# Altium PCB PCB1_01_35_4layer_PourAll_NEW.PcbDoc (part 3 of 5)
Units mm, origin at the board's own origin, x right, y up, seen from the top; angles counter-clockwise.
Board outline 26.5 x 17 mm, 4 copper layers (Top Layer, Layer 1, Layer 2, Bottom Layer), stack 0.603 mm thick; 0 components, 1 nets, 8 pads, 81 vias.

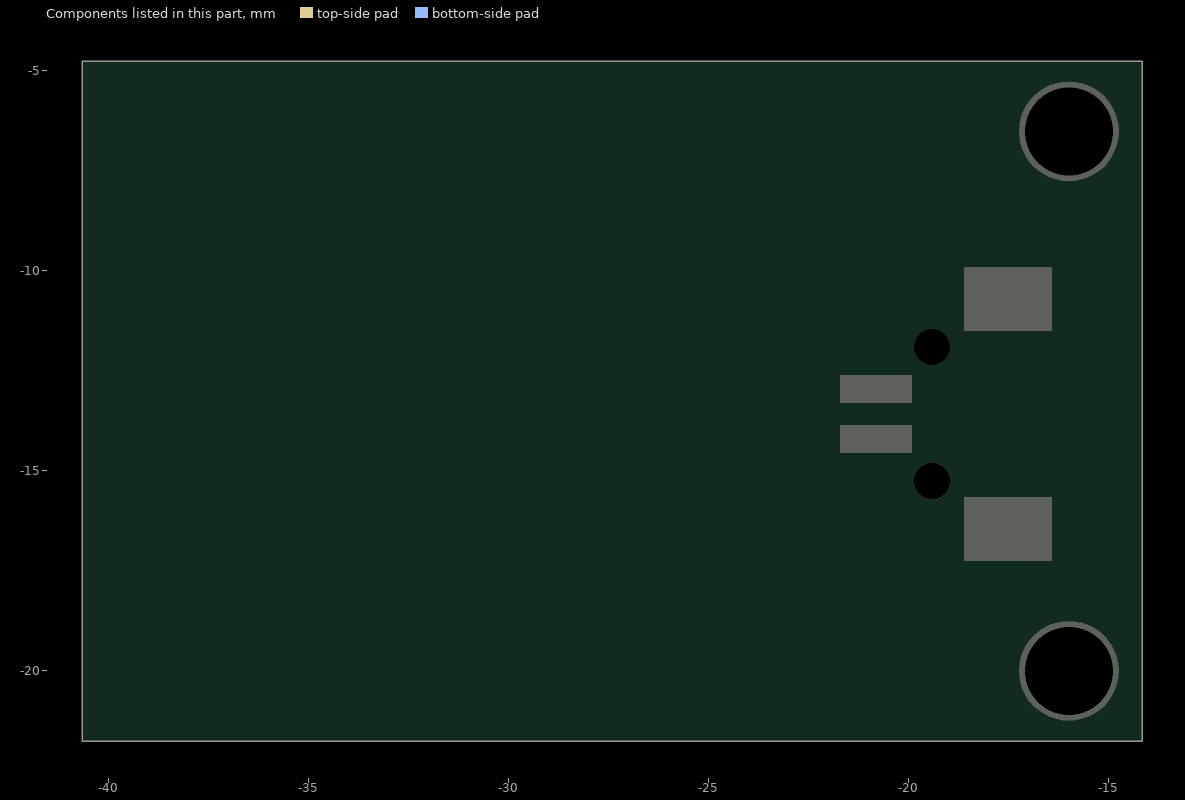
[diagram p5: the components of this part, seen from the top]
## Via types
v1: diameter 0.5, hole 0.3, Top Layer to Bottom Layer, tented both sides, 68 vias
v2: diameter 1, hole 0.5, Top Layer to Bottom Layer, 9 vias
v3: diameter 0.65, hole 0.3, Top Layer to Bottom Layer, 4 vias

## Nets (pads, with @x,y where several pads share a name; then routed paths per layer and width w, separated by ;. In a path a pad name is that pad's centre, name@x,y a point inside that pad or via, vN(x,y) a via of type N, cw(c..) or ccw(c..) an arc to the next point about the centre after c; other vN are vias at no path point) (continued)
copper on no net: (continued)
  Layer 2 w0.1: -34.932,-14.453 ccw(c-31.735,-13.27) -34.612,-15.099 ccw(c-31.883,-13.367) -34.162,-15.658 ccw(c-32.001,-13.479) -33.598,-16.1 ccw(c-31.896,-13.305) -32.95,-16.403 ccw(c-31.853,-13.187) -32.254,-16.561 ccw(c-31.856,-13.236) -31.541,-16.57 ccw(c-31.836,-13.435) -30.846,-16.424 ccw(c-31.819,-13.511) -30.204,-16.123 ccw(c-31.96,-13.292) -29.192,-15.147 ccw(c-31.916,-13.315) -28.864,-14.523 ccw(c-31.713,-13.393) -28.681,-13.844 ccw(c-31.734,-13.399) -28.66,-13.144 ccw(c-31.923,-13.413) -28.792,-12.456 ccw(c-31.977,-13.427) -29.065,-11.813 ccw(c-31.874,-13.368) -29.466,-11.243 ccw(c-31.708,-13.22) -29.984,-10.779 ccw(c-31.766,-13.312) -30.592,-10.446 ccw(c-31.831,-13.467) -31.257,-10.253 ccw(c-31.836,-13.485) -31.947,-10.203 ccw(c-31.859,-13.228) -33.269,-10.55 ccw(c-31.81,-13.294) -33.835,-10.937 ccw(c-31.719,-13.402) -34.305,-11.436 ccw(c-31.735,-13.393) -34.659,-12.021 ccw(c-31.894,-13.32) -34.879,-12.665 ccw(c-32.028,-13.286) -34.945,-13.342 ccw(c-31.832,-13.282) -34.858,-14.015 ccw(c-31.723,-13.258) -34.631,-14.653 ccw(c-31.772,-13.284) -34.276,-15.228 ccw(c-31.925,-13.405) -33.805,-15.71 ccw(c-31.965,-13.44) -33.238,-16.07 ccw(c-31.863,-13.222) -31.942,-16.384 ccw(c-31.86,-13.281) -31.276,-16.329 ccw(c-31.819,-13.487) -30.641,-16.13 ccw(c-31.843,-13.454) -30.07,-15.791 ccw(c-31.947,-13.314) -29.587,-15.337 ccw(c-31.979,-13.283) -29.211,-14.792 ccw(c-31.872,-13.339) -28.959,-14.181 ccw(c-31.672,-13.397) -28.851,-13.532 ccw(c-31.792,-13.396) -28.894,-12.877 ccw(c-31.943,-13.421) -29.077,-12.247 ccw(c-31.952,-13.422) -29.388,-11.671 ccw(c-31.754,-13.271) -30.337,-10.791 ccw(c-31.791,-13.358) -30.933,-10.535 ccw(c-31.83,-13.479) -31.57,-10.412 ccw(c-31.83,-13.452) -32.216,-10.426 ccw(c-31.853,-13.283) -32.843,-10.578 ccw(c-31.887,-13.174) -33.416,-10.869 ccw(c-31.747,-13.374) -34.303,-11.784 ccw(c-31.767,-13.369) -34.582,-12.359 ccw(c-31.946,-13.307) -34.728,-12.979 ccw(c-31.974,-13.295) -34.728,-13.614 ccw(c-31.755,-13.267) -34.321,-14.807 ccw(c-31.811,-13.306) -33.941,-15.31 ccw(c-31.957,-13.444) -33.46,-15.716 ccw(c-31.931,-13.392) -32.9,-15.999 ccw(c-31.874,-13.242) -32.293,-16.154 ccw(c-31.867,-13.209) -31.668,-16.178 ccw(c-31.857,-13.33) -31.054,-16.069 ccw(c-31.802,-13.516) -30.482,-15.826 ccw(c-31.869,-13.407) -29.982,-15.46 ccw(c-31.961,-13.303) -29.573,-14.996 ccw(c-31.96,-13.302) -29.271,-14.457 ccw(c-31.736,-13.385) -29.051,-13.256 ccw(c-31.839,-13.398) -29.149,-12.652 ccw(c-31.949,-13.427) -29.373,-12.083 ccw(c-31.92,-13.41) -29.711,-11.575 ccw(c-31.793,-13.302) -30.149,-11.154 ccw(c-31.734,-13.235) -30.67,-10.845 ccw(c-31.822,-13.443) -31.847,-10.601 ccw(c-31.827,-13.413) -32.445,-10.67 ccw(c-31.869,-13.235) -33.012,-10.867 ccw(c-31.865,-13.225) -33.517,-11.189 ccw(c-31.737,-13.379) -34.26,-12.114 ccw(c-31.806,-13.348) -34.468,-12.671 ccw(c-31.991,-13.302) -34.546,-13.258 ccw(c-31.919,-13.298) -34.489,-13.846 ccw(c-31.775,-13.268) -34.306,-14.406 ccw(c-31.753,-13.26) -34.009,-14.915 ccw(c-31.849,-13.333) -33.613,-15.347 ccw(c-31.967,-13.467) -33.131,-15.678 ccw(c-31.907,-13.349) -32.588,-15.891 ccw(c-31.873,-13.228) -32.013,-15.981 ccw(c-31.872,-13.236) -31.433,-15.95 ccw(c-31.847,-13.377) -30.876,-15.795 ccw(c-31.8,-13.504) -30.37,-15.518 ccw(c-31.894,-13.372) -29.94,-15.136 ccw(c-31.967,-13.304) -29.601,-14.671 ccw(c-31.933,-13.321) -29.369,-14.147 ccw(c-31.778,-13.37) -29.256,-13.588 ccw(c-31.713,-13.382) -29.274,-13.019 ccw(c-31.917,-13.416) -29.673,-11.963 ccw(c-31.887,-13.391) -30.029,-11.524 ccw(c-31.764,-13.265) -30.471,-11.175 ccw(c-31.764,-13.279) -30.98,-10.937 ccw(c-31.813,-13.421) -31.527,-10.817 ccw(c-31.819,-13.465) -32.086,-10.814 ccw(c-31.831,-13.37) -32.632,-10.929 ccw(c-31.887,-13.2) -33.136,-11.163 ccw(c-31.84,-13.269) -33.572,-11.504 ccw(c-31.747,-13.364) -33.924,-11.931 ccw(c-31.736,-13.374) -34.177,-12.421 ccw(c-31.933,-13.309) -34.339,-13.499 ccw(c-31.874,-13.294) -34.234,-14.035 ccw(c-31.767,-13.262) -34.017,-14.536 ccw(c-31.779,-13.271) -33.701,-14.978 ccw(c-31.882,-13.365) -33.298,-15.341 ccw(c-31.951,-13.455) -32.825,-15.602 ccw(c-31.893,-13.313) -32.307,-15.749 ccw(c-31.877,-13.226) -31.77,-15.783 ccw(c-31.873,-13.27) -31.24,-15.704 ccw(c-31.833,-13.42) -30.742,-15.512 ccw(c-31.818,-13.464) -30.302,-15.212 ccw(c-31.944,-13.323) -29.669,-14.368 ccw(c-31.899,-13.339) -29.501,-13.867 ccw(c-31.735,-13.374) -29.447,-13.343 ccw(c-31.763,-13.381) -29.515,-12.823 ccw(c-31.896,-13.412) -29.694,-12.331 ccw(c-31.928,-13.426) -29.972,-11.888 ccw(c-31.854,-13.366) -30.336,-11.516 ccw(c-31.748,-13.237) -30.773,-11.236 ccw(c-31.785,-13.32) -31.261,-11.064 ccw(c-31.813,-13.436) -31.773,-11.001 ccw(c-31.815,-13.443) -32.286,-11.046 ccw(c-31.863,-13.251) -33.216,-11.459 ccw(c-31.815,-13.301) -33.585,-11.809 ccw(c-31.74,-13.366) -33.87,-12.231 ccw(c-31.759,-13.358) -34.06,-12.701 ccw(c-31.89,-13.322) -34.144,-13.199 ccw(c-31.982,-13.313) -34.112,-13.701 ccw(c-31.797,-13.275) -33.728,-14.621 ccw(c-31.807,-13.288) -33.401,-14.999 ccw(c-31.908,-13.398) -33.001,-15.294 ccw(c-31.927,-13.418) -32.545,-15.49 ccw(c-31.881,-13.254) -31.566,-15.565 ccw(c-31.87,-13.306) -31.089,-15.447 ccw(c-31.815,-13.455) -30.651,-15.227 ccw(c-31.842,-13.423) -30.277,-14.914 ccw(c-31.931,-13.337) -29.98,-14.528 ccw(c-31.952,-13.323) -29.772,-14.09 ccw(c-31.862,-13.353) -29.662,-13.619 ccw(c-31.71,-13.371) -29.66,-13.136 ccw(c-31.805,-13.384) -29.768,-12.669 ccw(c-31.906,-13.419) -29.974,-12.236 ccw(c-31.907,-13.417) -30.265,-11.856 ccw(c-31.778,-13.282) -31.051,-11.334 ccw(c-31.798,-13.354) -31.51,-11.22 ccw(c-31.811,-13.44) -31.981,-11.206 ccw(c-31.814,-13.415) -32.444,-11.291 ccw(c-31.853,-13.291) -32.875,-11.473 ccw(c-31.884,-13.225) -33.252,-11.748 ccw(c-31.765,-13.349) -33.78,-12.506 ccw(c-31.788,-13.343) -33.913,-12.949 ccw(c-31.928,-13.319) -33.945,-13.409 ccw(c-31.938,-13.313) -33.871,-13.862 ccw(c-31.793,-13.27) -33.443,-14.664 ccw(c-31.835,-13.31) -33.115,-14.978 ccw(c-31.927,-13.431) -32.726,-15.21 ccw(c-31.929,-13.42) -32.296,-15.345 ccw(c-31.898,-13.236) -31.404,-15.325 ccw(c-31.89,-13.25) -30.982,-15.178 ccw(c-31.785,-13.449) -30.29,-14.632 ccw(c-31.837,-13.42) -30.059,-14.256 ccw(c-31.979,-13.355) -29.858,-13.405 ccw(c-31.913,-13.354) -29.894,-12.969 ccw(c-31.758,-13.323) -30.024,-12.554 ccw(c-31.691,-13.299) -30.246,-12.182 ccw(c-31.803,-13.385) -30.546,-11.871 ccw(c-31.872,-13.467) -30.905,-11.631 ccw(c-31.876,-13.471) -31.304,-11.471 ccw(c-31.848,-13.369) -31.726,-11.398 ccw(c-31.839,-13.206) -32.151,-11.422 ccw(c-31.831,-13.221) -32.557,-11.544 ccw(c-31.776,-13.347) -32.925,-11.753 ccw(c-31.73,-13.414) -33.241,-12.034 ccw(c-31.752,-13.396) -33.491,-12.372 ccw(c-31.863,-13.332) -33.662,-12.754 ccw(c-32.005,-13.286) -33.741,-13.164 ccw(c-31.916,-13.29) -33.722,-13.578 ccw(c-31.76,-13.262) -33.426,-14.346 ccw(c-31.792,-13.287) -33.168,-14.665 ccw(c-31.892,-13.389) -32.847,-14.92 ccw(c-31.948,-13.472) -32.478,-15.092 ccw(c-31.909,-13.353) -32.081,-15.175 ccw(c-31.898,-13.244) -31.675,-15.17 ccw(c-31.899,-13.224) -31.281,-15.083 ccw(c-31.87,-13.307) -30.915,-14.917 ccw(c-31.792,-13.437) -30.597,-14.674 ccw(c-31.78,-13.457) -30.346,-14.365 ccw(c-31.889,-13.387) -30.171,-14.009 ccw(c-31.971,-13.356) -30.076,-13.624 ccw(c-31.958,-13.357) -30.061,-13.23 ccw(c-31.848,-13.348) -30.13,-12.843 ccw(c-31.705,-13.306) -30.284,-12.484 ccw(c-31.75,-13.337) -30.516,-12.172 ccw(c-31.863,-13.447) -31.151,-11.735 ccw(c-31.86,-13.429) -31.52,-11.624 ccw(c-31.832,-13.235) -32.279,-11.657 ccw(c-31.81,-13.285) -32.63,-11.802 ccw(c-31.758,-13.381) -32.941,-12.019 ccw(c-31.739,-13.406) -33.199,-12.294 ccw(c-31.795,-13.364) -33.394,-12.616 ccw(c-31.921,-13.306) -33.513,-12.971 ccw(c-31.974,-13.29) -33.545,-13.342 ccw(c-31.855,-13.287) -33.492,-13.709 ccw(c-31.767,-13.265) -33.363,-14.055 ccw(c-31.765,-13.266) -33.167,-14.367 ccw(c-31.838,-13.324) -32.91,-14.629 ccw(c-31.927,-13.434) -32.603,-14.826 ccw(c-31.923,-13.415) -32.26,-14.945 ccw(c-31.898,-13.302) -31.9,-14.984 ccw(c-31.897,-13.235) -31.541,-14.948 ccw(c-31.89,-13.261) -31.199,-14.839 ccw(c-31.844,-13.363) -30.889,-14.66 ccw(c-31.769,-13.466) -30.63,-14.416 ccw(c-31.831,-13.417) -30.436,-14.121 ccw(c-31.95,-13.359) -30.258,-13.443 ccw(c-31.911,-13.358) -30.277,-13.093 ccw(c-31.788,-13.338) -30.371,-12.758 ccw(c-31.712,-13.31) -30.54,-12.456 ccw(c-31.798,-13.373) -30.773,-12.202 ccw(c-31.858,-13.44) -31.053,-12.003 ccw(c-31.866,-13.452) -31.368,-11.867 ccw(c-31.844,-13.378) -31.702,-11.8 ccw(c-31.833,-13.248) -32.041,-11.809 ccw(c-31.831,-13.233) -32.366,-11.897 ccw(c-31.791,-13.333) -32.662,-12.055 ccw(c-31.752,-13.393) -32.918,-12.271 ccw(c-31.762,-13.384) -33.123,-12.534 ccw(c-31.844,-13.334) -33.267,-12.832 ccw(c-31.963,-13.292) -33.339,-13.154 ccw(c-31.913,-13.294) -33.333,-13.482 ccw(c-31.785,-13.275) -33.116,-14.093 ccw(c-31.8,-13.288) -32.918,-14.35 ccw(c-31.916,-13.408) -32.385,-14.701 ccw(c-31.905,-13.36) -32.076,-14.774 ccw(c-31.893,-13.272) -31.758,-14.779 ccw(c-31.895,-13.248) -31.447,-14.719 ccw(c-31.876,-13.307) -31.157,-14.596 ccw(c-31.818,-13.41) -30.903,-14.413 ccw(c-31.792,-13.443) -30.7,-14.177 ccw(c-31.874,-13.388) -30.557,-13.903 ccw(c-31.941,-13.361) -30.475,-13.606 ccw(c-31.94,-13.36) -30.456,-13.299 ccw(c-31.859,-13.356) -30.501,-12.997 ccw(c-31.743,-13.325) -30.613,-12.714 ccw(c-31.759,-13.338) -30.787,-12.468 ccw(c-31.83,-13.4) -31.01,-12.266 ccw(c-31.862,-13.443) -31.269,-12.117 ccw(c-31.853,-13.419) -31.553,-12.024 ccw(c-31.833,-13.326) -31.847,-11.994 ccw(c-31.834,-13.221) -32.14,-12.033 ccw(c-31.816,-13.286) -32.413,-12.137 ccw(c-31.766,-13.379) -32.86,-12.505 ccw(c-31.795,-13.358) -33.015,-12.748 ccw(c-31.889,-13.312) -33.114,-13.018 ccw(c-31.95,-13.294) -33.146,-13.301 ccw(c-31.864,-13.294) -33.113,-13.583 ccw(c-31.794,-13.278) -33.021,-13.85 ccw(c-31.785,-13.275) -32.877,-14.092 ccw(c-31.837,-13.316) -32.687,-14.296 ccw(c-31.908,-13.399) -32.457,-14.452 ccw(c-31.915,-13.403) -32.199,-14.549 ccw(c-31.894,-13.32) -31.927,-14.586 ccw(c-31.892,-13.264) -31.654,-14.565 ccw(c-31.889,-13.277) -31.393,-14.489 ccw(c-31.857,-13.352) -31.156,-14.36 ccw(c-31.798,-13.437) -30.955,-14.181 ccw(c-31.832,-13.41) -30.803,-13.962 ccw(c-31.922,-13.364) -30.657,-13.456 ccw(c-31.903,-13.363) -30.665,-13.193 ccw(c-31.767,-13.338) -30.849,-12.71 ccw(c-31.798,-13.365) -31.018,-12.516 ccw(c-31.846,-13.416) -31.224,-12.363 ccw(c-31.855,-13.43) -31.456,-12.257 ccw(c-31.839,-13.38) -31.703,-12.201 ccw(c-31.828,-13.283) -31.955,-12.201 ccw(c-31.829,-13.252) -32.198,-12.26 ccw(c-31.802,-13.324) -32.42,-12.371 ccw(c-31.772,-13.372) -32.612,-12.527 ccw(c-31.775,-13.37) -32.768,-12.717 ccw(c-31.832,-13.334) -32.879,-12.935 ccw(c-31.923,-13.299) -32.938,-13.17 ccw(c-31.904,-13.299) -32.94,-13.411 ccw(c-31.809,-13.287) -32.791,-13.862 ccw(c-31.812,-13.291) -32.651,-14.053 ccw(c-31.87,-13.345) -32.475,-14.208 ccw(c-31.918,-13.413) -32.269,-14.318 ccw(c-31.899,-13.362) -32.046,-14.377 ccw(c-31.889,-13.282) -31.589,-14.346 ccw(c-31.879,-13.313) -31.378,-14.262 ccw(c-31.839,-13.388) -31.192,-14.135 ccw(c-31.837,-13.397) -31.041,-13.969 ccw(c-31.879,-13.365) -30.931,-13.774 ccw(c-31.859,-13.371) -30.847,-13.343 ; -34.932,-14.453 cw(c-31.726,-13.264) -35.11,-13.754 cw(c-31.881,-13.284) -35.134,-13.032 cw(c-32.049,-13.274) -34.993,-12.321 cw(c-31.842,-13.342) -34.696,-11.659 cw(c-31.712,-13.416) -34.262,-11.074 cw(c-31.732,-13.394) -33.715,-10.592 cw(c-31.836,-13.244) -33.076,-10.24 cw(c-31.878,-13.16) -32.371,-10.042 cw(c-31.841,-13.391) -31.638,-10.007 cw(c-31.842,-13.484) -30.226,-10.398 cw(c-31.729,-13.262) -29.616,-10.813 cw(c-31.739,-13.259) -29.117,-11.358 cw(c-31.919,-13.392) -28.748,-12.002 cw(c-31.951,-13.413) -28.451,-13.451 cw(c-31.67,-13.411) -28.546,-14.19 cw(c-31.77,-13.378) -28.809,-14.89 cw(c-31.953,-13.287) -29.219,-15.517 cw(c-31.986,-13.263) -29.752,-16.047 cw(c-31.9,-13.373) -30.385,-16.451 cw(c-31.808,-13.56) -31.096,-16.702 cw(c-31.846,-13.376) -31.846,-16.785 cw(c-31.848,-13.197) -32.599,-16.706 cw(c-31.851,-13.196) -33.32,-16.47 cw(c-31.922,-13.351) -33.974,-16.085 cw(c-32.016,-13.482) -34.525,-15.559 cw(c-31.835,-13.333) -34.944,-14.922 cw(c-31.704,-13.263) -35.219,-14.208 cw(c-31.744,-13.271) -35.339,-13.451 cw(c-31.941,-13.28) -35.291,-12.686 cw(c-32.017,-13.274) -35.068,-11.95 cw(c-31.793,-13.37) -34.687,-11.28 cw(c-31.722,-13.415) -33.546,-10.249 cw(c-31.86,-13.182) -32.835,-9.943 cw(c-31.861,-13.214) -32.07,-9.807 cw(c-31.845,-13.443) -31.293,-9.842 cw(c-31.841,-13.468) -29.842,-10.394 cw(c-31.684,-13.214) -29.241,-10.895 cw(c-31.785,-13.3) -28.769,-11.522 cw(c-31.962,-13.408) -28.443,-12.237 cw(c-31.993,-13.421) -28.274,-13.007 cw(c-31.838,-13.406) -28.273,-13.795 cw(c-31.718,-13.407) -28.799,-15.276 cw(c-31.98,-13.259) -29.292,-15.899 cw(c-31.975,-13.268) -29.906,-16.404 cw(c-31.874,-13.425) -30.615,-16.766 cw(c-31.816,-13.563) -31.39,-16.958 cw(c-31.848,-13.315) -32.189,-16.97 cw(c-31.837,-13.169) -32.975,-16.813 cw(c-31.855,-13.219) -33.712,-16.494 cw(c-31.962,-13.403) -34.362,-16.021 cw(c-31.991,-13.449) -34.888,-15.41 cw(c-31.783,-13.306) -35.266,-14.697 cw(c-31.718,-13.273) -35.537,-13.11 cw(c-32.01,-13.265) -35.409,-12.308 cw(c-31.957,-13.291) -35.099,-11.557 cw(c-31.751,-13.403) -34.631,-10.889 cw(c-31.738,-13.403) -33.329,-9.915 cw(c-31.875,-13.118) -32.549,-9.666 cw(c-31.851,-13.278) -31.731,-9.601 cw(c-31.855,-13.488) -30.915,-9.715 cw(c-31.858,-13.511) -30.14,-9.997 cw(c-31.781,-13.359) -29.443,-10.438 cw(c-31.728,-13.269) -28.43,-11.734 cw(c-32,-13.415) -28.157,-12.519 cw(c-31.978,-13.413) -28.054,-13.345 cw(c-31.776,-13.412) -28.132,-14.174 cw(c-31.643,-13.433) -28.398,-14.965 cw(c-31.882,-13.321) -28.835,-15.678 cw(c-31.997,-13.236) -29.415,-16.284 cw(c-31.956,-13.288) -30.11,-16.756 cw(c-31.85,-13.49) -30.892,-17.064 cw(c-31.833,-13.515) -31.725,-17.185 cw(c-31.842,-13.256) -32.567,-17.12 cw(c-31.838,-13.196) -34.12,-16.47 cw(c-32.013,-13.456) -34.755,-15.907 cw(c-31.941,-13.405) -35.244,-15.212 cw(c-31.733,-13.289) -35.572,-14.425 cw(c-31.677,-13.269) -35.728,-13.585 cw(c-31.827,-13.278) -35.701,-12.732 cw(c-32.07,-13.244) -35.484,-11.903 cw(c-31.895,-13.318) -35.082,-11.146 cw(c-31.719,-13.435) -34.526,-10.49 cw(c-31.708,-13.443) -33.843,-9.964 cw(c-31.803,-13.283) -33.064,-9.597 cw(c-31.872,-13.09) -32.219,-9.416 cw(c-31.849,-13.346) -31.354,-9.43 cw(c-31.869,-13.522) -30.509,-9.628 cw(c-31.855,-13.491) -29.723,-9.999 cw(c-31.74,-13.306) -29.036,-10.533 cw(c-31.664,-13.217) -28.488,-11.21 cw(c-31.897,-13.366) -28.104,-11.995 cw(c-32,-13.409) -27.867,-13.721 cw(c-31.704,-13.428) -28.033,-14.582 cw(c-31.7,-13.417) -28.393,-15.384 cw(c-31.929,-13.284) -28.922,-16.089 cw(c-31.968,-13.258) -30.363,-17.094 cw(c-31.833,-13.564) -31.214,-17.338 cw(c-31.843,-13.445) -32.1,-17.38 cw(c-31.83,-13.204) -32.976,-17.229 cw(c-31.819,-13.155) -33.803,-16.897 cw(c-31.899,-13.3) -34.54,-16.396 cw(c-32.061,-13.491) -35.147,-15.741 cw(c-31.882,-13.366) -35.589,-14.964 cw(c-31.688,-13.28) -35.856,-14.107 cw(c-31.687,-13.276) -35.937,-13.213 cw(c-31.89,-13.271) -35.825,-12.321 cw(c-32.08,-13.23) -35.512,-11.477 cw(c-31.836,-13.355) -35.016,-10.723 cw(c-31.698,-13.465) -34.369,-10.09 cw(c-31.725,-13.426) -33.604,-9.606 cw(c-31.827,-13.215) -32.751,-9.3 cw(c-31.844,-13.194) -31.847,-9.196 cw(c-31.841,-13.429) -30.942,-9.292 cw(c-31.848,-13.475) -30.075,-9.58 cw(c-31.779,-13.329) -29.291,-10.047 cw(c-31.729,-13.25) -28.63,-10.681 cw(c-31.907,-13.4) -28.124,-11.446 cw(c-31.952,-13.427) -27.791,-12.302 cw(c-31.798,-13.388) -27.65,-13.211 cw(c-31.693,-13.376) -27.718,-14.13 cw(c-31.927,-13.333) -27.986,-15.014 cw(c-31.98,-13.314) -28.437,-15.821 cw(c-31.855,-13.406) -29.052,-16.514 cw(c-31.771,-13.488) -29.808,-17.051 cw(c-31.889,-13.279) -30.665,-17.409 cw(c-31.909,-13.219) -31.581,-17.578 cw(c-31.901,-13.371) -32.513,-17.545 cw(c-31.913,-13.499) -33.415,-17.304 cw(c-31.825,-13.273) -34.243,-16.868 cw(c-31.789,-13.215) -34.961,-16.266 cw(c-31.899,-13.316) -35.533,-15.523 cw(c-32.015,-13.394) -35.925,-14.668 cw(c-31.783,-13.317) -36.118,-13.747 cw(c-31.771,-13.306) -35.903,-11.883 cw(c-31.998,-13.243) -35.491,-11.031 cw(c-31.789,-13.373) -34.901,-10.289 cw(c-31.768,-13.381) -33.316,-9.261 cw(c-31.866,-13.158) -32.392,-9.033 cw(c-31.834,-13.403) -31.438,-9.016 cw(c-31.828,-13.432) -29.624,-9.585 cw(c-31.713,-13.207) -28.854,-10.156 cw(c-31.882,-13.388) -28.229,-10.884 cw(c-31.907,-13.416) -27.507,-12.656 cw(c-31.652,-13.36) -27.455,-13.619 cw(c-31.9,-13.345) -27.619,-14.571 cw(c-31.945,-13.341) -28.53,-16.268 cw(c-31.734,-13.507) -29.244,-16.925 cw(c-31.88,-13.307) -30.087,-17.409 cw(c-31.909,-13.262) -31.987,-17.791 cw(c-31.903,-13.538) -32.955,-17.659 cw(c-31.842,-13.3) -33.871,-17.316 cw(c-31.822,-13.241) -35.385,-16.087 cw(c-31.936,-13.363) -36.226,-14.322 cw(c-31.749,-13.298) -36.244,-12.36 cw(c-31.924,-13.284) -35.415,-10.576 cw(c-31.748,-13.393) -33.905,-9.303 cw(c-31.852,-13.241) -31.99,-8.802 cw(c-31.823,-13.455) -30.035,-9.157 cw(c-31.768,-13.269) -28.419,-10.32 cw(c-31.921,-13.434) -27.44,-12.063 cw(c-31.735,-13.357) -27.305,-14.062 cw(c-31.967,-13.342) -28.028,-15.939 cw(c-31.783,-13.442) -29.491,-17.325 cw(c-31.923,-13.247) -31.41,-17.968 cw(c-31.885,-13.549) -32.43,-17.959 cw(c-31.854,-13.337) -33.423,-17.723 cw(c-31.819,-13.22) -35.152,-16.647 cw(c-32.029,-13.443) -35.799,-15.851 cw(c-31.852,-13.336) -36.253,-14.93 cw(c-31.732,-13.286) -36.527,-12.9 cw(c-32.038,-13.266) -36.326,-11.888 cw(c-31.851,-13.332) -35.902,-10.945 cw(c-31.728,-13.398) -34.504,-9.432 cw(c-31.907,-13.149) -33.591,-8.938 cw(c-31.843,-13.327) -32.589,-8.662 cw(c-31.813,-13.495) -31.548,-8.607 cw(c-31.805,-13.42) -30.519,-8.775 cw(c-31.736,-13.176) -29.551,-9.167 cw(c-31.828,-13.331) -28.695,-9.767 cw(c-31.942,-13.465) -27.985,-10.538 cw(c-31.885,-13.427) -27.456,-11.443 cw(c-31.651,-13.324) -27.138,-12.445 cw(c-31.819,-13.349) -27.054,-13.493 cw(c-32.002,-13.347) -27.197,-14.537 cw(c-31.94,-13.365) -27.559,-15.528 cw(c-31.712,-13.48) -28.132,-16.416 cw(c-31.829,-13.373) -28.89,-17.154 cw(c-31.947,-13.226) -29.792,-17.712 cw(c-31.925,-13.28) -30.792,-18.067 cw(c-31.868,-13.53) -31.847,-18.193 cw(c-31.86,-13.383) -32.905,-18.078 cw(c-31.821,-13.192) -33.915,-17.737 cw(c-31.846,-13.239) -34.831,-17.189 cw(c-32.002,-13.442) -35.605,-16.452 cw(c-31.892,-13.363) -36.194,-15.559 cw(c-31.715,-13.268) -36.578,-14.557 cw(c-31.761,-13.277) -36.74,-13.496 cw(c-32.016,-13.286) -36.666,-12.424 cw(c-31.898,-13.318) -36.351,-11.394 cw(c-31.706,-13.398) -35.821,-10.455 cw(c-31.738,-13.371) -35.103,-9.649 cw(c-31.907,-13.18) -34.224,-9.019 cw(c-31.863,-13.281) -33.225,-8.603 cw(c-31.801,-13.485) -32.157,-8.412 cw(c-31.799,-13.449) -31.072,-8.452 cw(c-31.761,-13.199) -30.02,-8.73 cw(c-31.806,-13.284) -29.057,-9.237 cw(c-31.926,-13.468) -28.225,-9.942 cw(c-31.903,-13.45) -27.561,-10.809 cw(c-31.686,-13.321) -27.101,-11.801 cw(c-31.768,-13.336) -26.877,-12.873 cw(c-31.992,-13.36) -26.89,-13.969 cw(c-31.969,-13.367) -27.136,-15.04 cw(c-31.734,-13.451) -27.61,-16.032 cw(c-31.785,-13.405) -28.297,-16.892 cw(c-31.951,-13.243) -29.155,-17.585 cw(c-31.945,-13.26) -30.142,-18.081 cw(c-31.861,-13.492) -31.215,-18.349 cw(c-31.855,-13.438) -32.321,-18.369 cw(c-31.836,-13.201) -33.408,-18.148 cw(c-31.843,-13.211) -34.425,-17.7 cw(c-31.967,-13.422) -35.32,-17.042 cw(c-31.932,-13.402) -36.045,-16.197 cw(c-31.732,-13.263) -36.57,-15.213 cw(c-31.738,-13.261) -36.875,-14.138 cw(c-31.977,-13.299) -36.939,-13.023 cw(c-31.955,-13.313) -36.749,-11.92 cw(c-31.715,-13.38) -36.323,-10.882 cw(c-31.711,-13.378) -35.686,-9.957 cw(c-31.891,-13.219) -34.862,-9.193 cw(c-31.897,-13.233) -33.886,-8.633 cw(c-31.793,-13.466) -32.809,-8.298 cw(c-31.787,-13.474) -31.684,-8.199 cw(c-31.78,-13.237) -30.564,-8.347 cw(c-31.79,-13.227) -29.505,-8.744 cw(c-31.906,-13.461) -28.555,-9.364 cw(c-31.913,-13.475) -27.758,-10.172 cw(c-31.729,-13.332) -27.155,-11.135 cw(c-31.713,-13.31) -26.783,-12.21 cw(c-31.973,-13.371) -26.655,-13.343 cw(c-31.994,-13.375) -26.77,-14.479 cw(c-31.77,-13.425) -27.129,-15.563 cw(c-31.729,-13.43) -27.724,-16.54 cw(c-31.946,-13.266) -28.52,-17.365 cw(c-31.967,-13.246) -29.473,-18.003 cw(c-31.865,-13.448) -30.543,-18.42 cw(c-31.839,-13.498) -31.682,-18.585 cw(c-31.85,-13.221) -32.83,-18.498 cw(c-31.848,-13.186) -33.936,-18.168 cw(c-31.936,-13.39) -34.945,-17.606 cw(c-31.968,-13.454) -35.802,-16.831 cw(c-31.757,-13.265) -36.47,-15.885 cw(c-31.723,-13.241) -36.923,-14.817 cw(c-31.933,-13.302) -37.134,-13.676 cw(c-32.018,-13.32) -37.083,-12.514 cw(c-31.734,-13.362) -36.778,-11.391 cw(c-31.687,-13.376) -36.241,-10.356 cw(c-31.864,-13.255) -35.493,-9.461 cw(c-31.943,-13.189) -34.56,-8.756 cw(c-31.792,-13.439) -33.495,-8.272 cw(c-31.771,-13.491) -32.349,-8.025 cw(c-31.79,-13.281) -31.176,-8.031 cw(c-31.787,-13.163) -30.033,-8.302 cw(c-31.885,-13.443) -28.975,-8.818 cw(c-31.915,-13.498) -28.05,-9.547 cw(c-31.768,-13.352) -27.303,-10.459 cw(c-31.662,-13.272) -26.78,-11.518 cw(c-31.944,-13.376) -26.502,-12.668 cw(c-32.013,-13.389) -26.474,-13.852 cw(c-31.811,-13.409) -26.702,-15.015 cw(c-31.668,-13.444) -27.187,-16.098 cw(c-31.93,-13.291) -27.899,-17.05 cw(c-31.989,-13.242) -28.799,-17.83 cw(c-31.879,-13.407) -29.845,-18.399 cw(c-31.81,-13.553) -30.995,-18.718 cw(c-31.86,-13.25) -32.189,-18.776 cw(c-31.858,-13.166) -33.369,-18.579 cw(c-31.914,-13.352) -34.48,-18.132 cw(c-31.99,-13.511) -35.464,-17.447 cw(c-31.787,-13.278) -36.274,-16.559 cw(c-31.785,-13.261) -37.243,-14.372 cw(c-32.075,-13.339) -37.343,-13.171 cw(c-31.764,-13.348) -37.174,-11.975 cw(c-31.74,-13.341) -36.101,-9.823 cw(c-31.993,-13.16) -35.235,-8.977 cw(c-31.801,-13.406) -34.201,-8.341 cw(c-31.777,-13.429) -31.847,-7.794 cw(c-31.798,-13.108) -30.636,-7.922 cw(c-31.865,-13.414) -29.482,-8.316 cw(c-31.872,-13.456) -27.55,-9.788 cw(c-31.629,-13.229) -26.873,-10.808 cw(c-31.908,-13.372) -26.439,-11.954 cw(c-31.954,-13.396) -26.341,-14.394 cw(c-31.617,-13.441) -26.697,-15.571 cw(c-31.903,-13.317) -27.307,-16.641 cw(c-31.959,-13.29) -29.134,-18.279 cw(c-31.775,-13.587) -30.273,-18.758 cw(c-31.861,-13.29) -31.492,-18.972 cw(c-31.876,-13.218) -33.931,-18.606 cw(c-31.923,-13.426) -35.978,-17.223 cw(c-31.766,-13.239) -37.257,-15.1 cw(c-31.966,-13.337) -37.498,-12.63 cw(c-31.711,-13.341) -36.673,-10.28 cw(c-31.923,-13.242) -34.915,-8.51 cw(c-31.758,-13.451) -32.566,-7.644 cw(c-31.817,-13.214) -30.07,-7.872 cw(c-31.876,-13.484) -27.895,-9.136 cw(c-31.723,-13.28) -26.473,-11.215 cw(c-31.978,-13.411) -26.059,-13.708 cw(c-31.714,-13.401) -26.757,-16.141 cw(c-31.985,-13.282) -28.422,-18.058 cw(c-31.749,-13.586) -29.529,-18.699 cw(c-31.852,-13.337) -30.753,-19.076 cw(c-31.887,-13.194) -33.304,-19.014 cw(c-31.972,-13.571) -34.509,-18.568 cw(c-31.849,-13.342) -35.585,-17.862 cw(c-31.755,-13.215) -37.171,-15.847 cw(c-32.1,-13.39) -37.597,-14.629 cw(c-31.855,-13.341) -37.74,-13.344 cw(c-31.686,-13.334) -37.195,-10.825 cw(c-32.041,-13.179) -36.525,-9.715 cw(c-31.857,-13.33) -35.622,-8.781 cw(c-31.736,-13.464) -33.323,-7.59 cw(c-31.842,-13.093) -32.034,-7.398 cw(c-31.843,-13.319) -30.733,-7.499 cw(c-31.879,-13.533) -29.482,-7.879 cw(c-31.84,-13.452) -28.339,-8.516 cw(c-31.654,-13.192) -27.364,-9.391 cw(c-31.819,-13.326) -26.61,-10.463 cw(c-32.014,-13.438) -26.102,-11.675 cw(c-31.933,-13.418) -25.864,-12.967 cw(c-31.613,-13.396) -25.916,-14.282 cw(c-31.809,-13.356) -26.263,-15.553 cw(c-32.025,-13.274) -26.877,-16.721 cw(c-31.964,-13.32) -27.725,-17.734 cw(c-31.743,-13.554) -28.776,-18.535 cw(c-31.829,-13.389) -29.982,-19.081 cw(c-31.907,-13.163) -31.279,-19.354 cw(c-31.904,-13.232) -32.606,-19.346 cw(c-31.943,-13.551) -33.9,-19.045 cw(c-31.875,-13.394) -35.094,-18.461 cw(c-31.746,-13.184) -36.136,-17.632 cw(c-31.793,-13.225) -36.979,-16.599 cw(c-32.063,-13.397) -37.576,-15.406 cw(c-31.913,-13.356) -37.888,-14.107 cw(c-31.662,-13.32) -37.913,-12.769 cw(c-31.716,-13.311) -37.654,-11.455 cw(c-32.019,-13.213) -37.112,-10.229 cw(c-31.906,-13.295) -36.307,-9.156 cw(c-31.713,-13.471) -35.287,-8.28 cw(c-31.736,-13.429) -34.104,-7.64 cw(c-31.854,-13.135) -32.808,-7.274 cw(c-31.848,-13.257) -31.462,-7.209 cw(c-31.861,-13.525) -30.131,-7.438 cw(c-31.846,-13.488) -28.878,-7.944 cw(c-31.694,-13.212) -27.765,-8.713 cw(c-31.774,-13.282) -26.853,-9.713 cw(c-31.995,-13.447) -26.178,-10.89 cw(c-31.963,-13.438) -25.767,-12.184 cw(c-31.657,-13.379) -25.649,-13.538 cw(c-31.744,-13.362) -25.84,-14.884 cw(c-32.019,-13.295) -26.318,-16.16 cw(c-31.998,-13.31) -27.057,-17.307 cw(c-31.76,-13.507) -28.029,-18.265 cw(c-31.791,-13.443) -29.194,-18.98 cw(c-31.918,-13.182) -30.488,-19.426 cw(c-31.918,-13.2) -31.848,-19.588 cw(c-31.918,-13.505) -33.212,-19.449 cw(c-31.892,-13.459) -34.511,-19.006 cw(c-31.769,-13.189) -35.685,-18.29 cw(c-31.778,-13.194) -36.681,-17.341 cw(c-32.011,-13.386) -37.447,-16.196 cw(c-31.975,-13.385) -37.936,-14.907 cw(c-31.682,-13.306) -38.133,-13.54 cw(c-31.683,-13.302) -38.036,-12.161 cw(c-31.976,-13.246) -37.641,-10.836 cw(c-31.97,-13.266) -36.956,-9.632 cw(c-31.716,-13.446) -36.024,-8.604 cw(c-31.708,-13.447) -34.895,-7.797 cw(c-31.85,-13.19) -33.616,-7.254 cw(c-31.867,-13.189) -32.246,-7.013 cw(c-31.843,-13.506) -30.854,-7.076 cw(c-31.841,-13.521) -29.506,-7.433 cw(c-31.734,-13.251) -28.267,-8.075 ; v3(-31.5,-12.823) -31.373,-12.823 -30.853,-13.343 ; -28.267,-8.075 cw(c-31.733,-13.222) -27.203,-8.981 cw(c-31.968,-13.446) -26.361,-10.099 cw(c-31.985,-13.462) -25.775,-11.371 cw(c-31.713,-13.374) -25.478,-12.741 cw(c-31.671,-13.354) -25.498,-14.144 cw(c-31.999,-13.316) -25.824,-15.511 cw(c-32.03,-13.31) -26.434,-16.78 cw(c-31.793,-13.461) -27.304,-17.886 cw(c-31.737,-13.495) -28.402,-18.769 cw(c-31.921,-13.212) -29.669,-19.392 cw(c-31.939,-13.176) -31.041,-19.732 cw(c-31.905,-13.451) -32.454,-19.767 cw(c-31.897,-13.534) -33.841,-19.483 cw(c-31.794,-13.207) -35.134,-18.901 cw(c-31.774,-13.163) -36.275,-18.057 cw(c-31.961,-13.361) -37.207,-16.986 cw(c-32.036,-13.43) -37.875,-15.73 cw(c-31.712,-13.299) -38.252,-14.357 cw(c-31.658,-13.285) -38.329,-12.934 cw(c-31.924,-13.268) -38.097,-11.527 cw(c-32.044,-13.248) -37.554,-10.207 cw(c-31.732,-13.417) -36.732,-9.036 cw(c-31.68,-13.455) -35.68,-8.065 cw(c-31.833,-13.243) -34.443,-7.344 cw(c-31.901,-13.121) -33.073,-6.919 cw(c-31.831,-13.474) -31.642,-6.805 cw(c-31.829,-13.547) -30.217,-6.998 cw(c-31.764,-13.299) -28.867,-7.494 cw(c-31.704,-13.152) -27.661,-8.282 cw(c-31.935,-13.434) -26.657,-9.317 cw(c-31.996,-13.488) -25.894,-10.543 cw(c-31.768,-13.382) -25.413,-11.905 cw(c-31.599,-13.331) -25.251,-13.342 cw(c-31.967,-13.333) -25.409,-14.782 cw(c-32.056,-13.319) -25.87,-16.157 cw(c-31.835,-13.425) -26.616,-17.401 cw(c-31.674,-13.533) -27.624,-18.447 cw(c-31.913,-13.248) -28.839,-19.246 cw(c-31.962,-13.163) -30.198,-19.769 cw(c-31.904,-13.395) -31.638,-19.988 cw(c-31.886,-13.606) -33.093,-19.878 cw(c-31.817,-13.238) -34.489,-19.449 cw(c-31.779,-13.138) -35.764,-18.732 cw(c-31.918,-13.326) -36.855,-17.758 cw(c-32.082,-13.485) -37.701,-16.562 cw(c-31.753,-13.302) -38.263,-15.207 cw(c-31.738,-13.282) -38.469,-12.294 cw(c-32.113,-13.249) -38.085,-10.874 cw(c-31.761,-13.387) -37.396,-9.572 cw(c-31.726,-13.393) -35.274,-7.548 cw(c-31.946,-13.072) -33.929,-6.936 cw(c-31.828,-13.431) -32.481,-6.636 cw(c-31.81,-13.474) -29.557,-6.983 cw(c-31.697,-13.089) -28.223,-7.631 cw(c-31.899,-13.408) -27.064,-8.559 cw(c-31.929,-13.458) -25.46,-11.044 cw(c-31.549,-13.296) -25.107,-12.491 cw(c-31.923,-13.344) -25.084,-13.982 cw(c-31.993,-13.351) -25.981,-16.813 cw(c-31.618,-13.546) -26.874,-18.012 cw(c-31.891,-13.29) -28.012,-18.984 cw(c-31.948,-13.23) -30.777,-20.102 cw(c-31.868,-13.474) -33.757,-19.92 cw(c-31.821,-13.189) -36.391,-18.497 cw(c-31.969,-13.414) -38.158,-16.075 cw(c-31.706,-13.264) -38.743,-13.126 cw(c-31.987,-13.292) -38,-10.209 cw(c-31.693,-13.405) -36.092,-7.869 cw(c-31.9,-13.195) -33.36,-6.577 cw(c-31.797,-13.506) -30.329,-6.556 cw(c-31.763,-13.201) -27.581,-7.842 cw(c-31.945,-13.488) -25.625,-10.174 cw(c-31.677,-13.316) -24.861,-13.123 cw(c-32.025,-13.358) -25.413,-16.128 cw(c-31.712,-13.462) -27.205,-18.607 cw(c-31.974,-13.211) -29.884,-20.102 cw(c-31.83,-13.655) -31.404,-20.376 cw(c-31.843,-13.341) -32.948,-20.302 cw(c-31.824,-13.157) -35.819,-19.187 cw(c-32.076,-13.552) -37.004,-18.186 cw(c-31.85,-13.35) -37.935,-16.945 cw(c-31.685,-13.242) -38.909,-14.01 cw(c-32.149,-13.298) -38.894,-12.453 cw(c-31.864,-13.343) -38.53,-10.938 cw(c-31.663,-13.406) -36.882,-8.307 cw(c-32.001,-13.085) -35.668,-7.322 cw(c-31.862,-13.321) -34.263,-6.635 cw(c-31.77,-13.561) -32.741,-6.264 cw(c-31.78,-13.449) -31.173,-6.225 cw(c-31.746,-13.066) -29.635,-6.534 cw(c-31.835,-13.309) -28.204,-7.181 cw(c-31.966,-13.539) -26.943,-8.122 cw(c-31.892,-13.467) -25.91,-9.31 cw(c-31.574,-13.248) -25.164,-10.697 cw(c-31.804,-13.328) -24.749,-12.218 cw(c-32.073,-13.375) -24.67,-13.795 cw(c-31.979,-13.385) -24.928,-15.354 cw(c-31.607,-13.492) -25.524,-16.819 cw(c-31.799,-13.372) -26.435,-18.113 cw(c-32.014,-13.189) -27.604,-19.184 cw(c-31.967,-13.262) -28.975,-19.981 cw(c-31.812,-13.616) -30.49,-20.458 cw(c-31.839,-13.409) -32.073,-20.582 cw(c-31.834,-13.118) -33.65,-20.362 cw(c-31.858,-13.192) -35.144,-19.812 cw(c-32.032,-13.536) -36.482,-18.946 cw(c-31.9,-13.398) -37.592,-17.8 cw(c-31.666,-13.212) -38.43,-16.44 cw(c-31.731,-13.237) -38.96,-14.932 cw(c-32.105,-13.321) -39.147,-13.343 cw(c-31.935,-13.336) -38.971,-11.752 cw(c-31.633,-13.399) -38.454,-10.233 cw(c-31.686,-13.369) -37.627,-8.858 cw(c-31.987,-13.136) -36.518,-7.697 cw(c-31.903,-13.262) -35.174,-6.815 cw(c-31.756,-13.541) -33.67,-6.243 cw(c-31.764,-13.49) -32.077,-6.003 cw(c-31.776,-13.113) -30.469,-6.117 cw(c-31.816,-13.237) -28.927,-6.592 cw(c-31.941,-13.537) -27.521,-7.39 cw(c-31.912,-13.506) -26.317,-8.469 cw(c-31.631,-13.258) -25.376,-9.786 cw(c-31.735,-13.296) -24.757,-11.282 cw(c-32.054,-13.392) -24.475,-12.88 cw(c-32.02,-13.395) -24.539,-14.502 cw(c-31.654,-13.453) -24.956,-16.071 cw(c-31.729,-13.405) -25.716,-17.508 cw(c-32.014,-13.216) -26.772,-18.748 cw(c-32.001,-13.237) -28.067,-19.736 cw(c-31.815,-13.553) -29.548,-20.419 cw(c-31.818,-13.485) -31.146,-20.75 cw(c-31.854,-13.137) -32.78,-20.727 cw(c-31.862,-13.151) -34.373,-20.357 cw(c-31.985,-13.492) -35.849,-19.648 cw(c-31.945,-13.465) -37.127,-18.624 cw(c-31.695,-13.209) -38.154,-17.345 cw(c-31.703,-13.208) -38.888,-15.876 cw(c-32.039,-13.328) -39.284,-14.282 cw(c-32.016,-13.344) -39.31,-12.639 cw(c-31.651,-13.375) -38.978,-11.026 cw(c-31.646,-13.371) -38.311,-9.519 cw(c-31.949,-13.191) -37.332,-8.192 cw(c-31.963,-13.204) -36.077,-7.12 cw(c-31.75,-13.511) -34.617,-6.345 cw(c-31.74,-13.521) -33.025,-5.897 cw(c-31.793,-13.178) -31.373,-5.806 cw(c-31.811,-13.153) -29.741,-6.09 cw(c-31.914,-13.52) -28.208,-6.723 cw(c-31.92,-13.543) -26.843,-7.668 cw(c-31.693,-13.287) -25.715,-8.888 cw(c-31.666,-13.245) -24.89,-10.331 cw(c-32.022,-13.402) -24.399,-11.922 cw(c-32.053,-13.414) -24.257,-13.583 cw(c-31.717,-13.426) -24.478,-15.235 cw(c-31.645,-13.425) -25.067,-16.796 cw(c-31.999,-13.248) -25.983,-18.194 cw(c-32.036,-13.225) -27.177,-19.366 cw(c-31.834,-13.487) -28.596,-20.252 cw(c-31.778,-13.563) -30.18,-20.796 cw(c-31.869,-13.17) -31.847,-20.981 cw(c-31.875,-13.118) -33.517,-20.808 cw(c-31.947,-13.434) -35.11,-20.277 cw(c-31.98,-13.546) -36.544,-19.401 cw(c-31.731,-13.22) -37.754,-18.23 cw(c-31.687,-13.176) -38.688,-16.827 cw(c-31.972,-13.319) -39.297,-15.256 cw(c-32.1,-13.37) -39.537,-13.586 cw(c-31.684,-13.354) -39.405,-11.901 cw(c-31.612,-13.362) -38.918,-10.282 cw(c-31.898,-13.237) -38.092,-8.805 cw(c-32.037,-13.156) -36.954,-7.551 cw(c-31.756,-13.471) -35.567,-6.576 cw(c-31.712,-13.54) -34.003,-5.917 cw(c-31.795,-13.246) -32.333,-5.611 cw(c-31.823,-13.066) -30.636,-5.688 cw(c-31.887,-13.488) -28.994,-6.137 cw(c-31.916,-13.576) -27.484,-6.925 cw(c-31.746,-13.33) -26.179,-8.02 cw(c-31.609,-13.179) -25.152,-9.383 cw(c-31.979,-13.401) -24.45,-10.939 cw(c-32.074,-13.438) -24.093,-12.611 cw(c-31.783,-13.413) -24.105,-14.321 cw(c-31.559,-13.426) -24.502,-15.986 cw(c-31.97,-13.281) -25.256,-17.525 cw(c-32.067,-13.225) -26.321,-18.871 cw(c-31.867,-13.429) -27.651,-19.955 cw(c-31.724,-13.628) -29.192,-20.714 cw(c-31.875,-13.215) -30.865,-21.115 cw(c-31.896,-13.095) -32.586,-21.152 cw(c-31.925,-13.372) -34.276,-20.817 cw(c-31.993,-13.627) -35.849,-20.111 cw(c-31.77,-13.247) -37.229,-19.075 cw(c-31.771,-13.221) -39.18,-16.246 cw(c-32.168,-13.412) -39.641,-14.578 cw(c-31.731,-13.342) -39.722,-12.848 cw(c-31.698,-13.326) -38.783,-9.53 cw(c-32.111,-13.133) -37.788,-8.106 cw(c-31.778,-13.426) -36.502,-6.937 cw(c-31.737,-13.454) -33.335,-5.541 cw(c-31.853,-12.998) -31.598,-5.399 cw(c-31.867,-13.441) -29.871,-5.646 cw(c-31.866,-13.504) -26.766,-7.202 cw(c-31.613,-13.152) -25.545,-8.454 cw(c-31.935,-13.405) -24.628,-9.946 -24.611,-9.955 cw(c-32.043,-13.48) -23.976,-11.875 ; -23.962,-11.903 v2(-23.089,-12.776)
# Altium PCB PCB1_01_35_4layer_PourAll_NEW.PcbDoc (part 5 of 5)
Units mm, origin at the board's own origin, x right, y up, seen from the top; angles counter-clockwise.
Board outline 26.5 x 17 mm, 4 copper layers (Top Layer, Layer 1, Layer 2, Bottom Layer), stack 0.603 mm thick; 0 components, 1 nets, 8 pads, 81 vias.

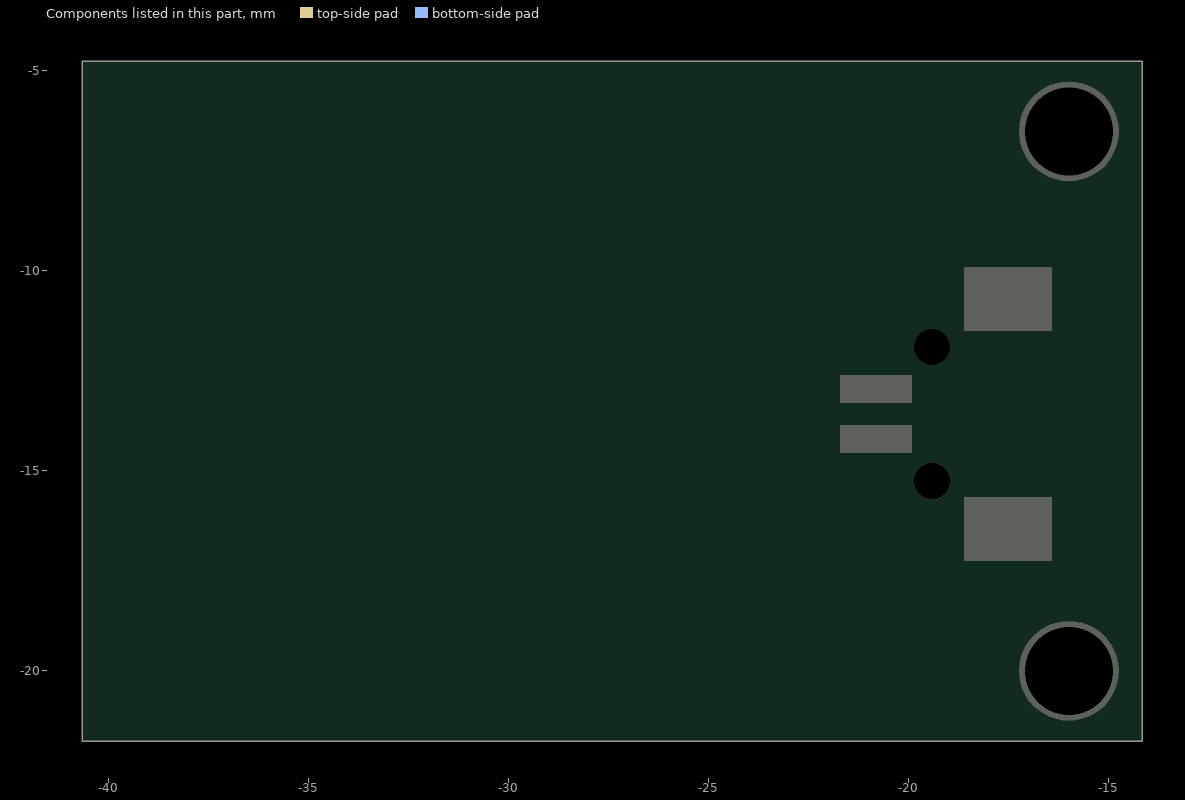
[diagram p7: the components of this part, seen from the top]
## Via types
v1: diameter 0.5, hole 0.3, Top Layer to Bottom Layer, tented both sides, 68 vias
v2: diameter 1, hole 0.5, Top Layer to Bottom Layer, 9 vias
v3: diameter 0.65, hole 0.3, Top Layer to Bottom Layer, 4 vias

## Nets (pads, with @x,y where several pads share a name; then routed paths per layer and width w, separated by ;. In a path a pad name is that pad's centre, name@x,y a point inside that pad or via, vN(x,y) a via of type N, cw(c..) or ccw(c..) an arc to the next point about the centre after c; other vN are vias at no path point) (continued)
copper on no net: (continued)
  Bottom Layer w0.1: v3(-31.5,-12.823) -31.508,-12.815 -32.084,-12.815 v3(-32.092,-12.806) -32.393,-13.107 -32.568,-13.107 -32.861,-13.4 ccw(c-31.846,-13.271) -32.802,-13.635 ccw(c-31.754,-13.236) -32.691,-13.852 ccw(c-31.698,-13.2) -32.535,-14.043 ccw(c-31.695,-13.198) -32.342,-14.198 ccw(c-31.725,-13.245) -32.121,-14.31 ccw(c-31.751,-13.317) -31.878,-14.369 ccw(c-31.751,-13.287) -31.626,-14.369 ccw(c-31.762,-13.19) -31.379,-14.313 ccw(c-31.778,-13.14) -31.147,-14.206 ccw(c-31.768,-13.154) -30.941,-14.054 ccw(c-31.721,-13.205) -30.772,-13.859 ccw(c-31.689,-13.232) -30.587,-13.377 ccw(c-31.826,-13.207) -30.579,-13.114 ccw(c-31.845,-13.206) -30.726,-12.608 ccw(c-31.754,-13.159) -30.878,-12.389 ccw(c-31.72,-13.132) -31.078,-12.21 ccw(c-31.78,-13.218) -31.315,-12.081 ccw(c-31.811,-13.293) -31.577,-12.005 ccw(c-31.815,-13.306) -31.849,-11.984 ccw(c-31.817,-13.25) -32.121,-12.02 ccw(c-31.838,-13.166) -32.379,-12.117 ccw(c-31.831,-13.171) -32.609,-12.274 ccw(c-31.76,-13.254) -32.799,-12.478 ccw(c-31.708,-13.294) -32.944,-12.72 ccw(c-31.716,-13.292) -33.036,-12.987 ccw(c-31.787,-13.276) -33.069,-13.268 ccw(c-31.873,-13.275) -33.036,-13.552 ccw(c-31.812,-13.258) -32.938,-13.821 ccw(c-31.718,-13.212) -32.782,-14.065 ccw(c-31.688,-13.191) -32.335,-14.432 ccw(c-31.738,-13.284) -32.062,-14.537 ccw(c-31.757,-13.349) -31.77,-14.576 ccw(c-31.756,-13.244) -31.475,-14.546 ccw(c-31.775,-13.15) -31.192,-14.453 ccw(c-31.784,-13.127) -30.932,-14.303 ccw(c-31.753,-13.17) -30.709,-14.102 ccw(c-31.682,-13.232) -30.536,-13.856 ccw(c-31.666,-13.245) -30.424,-13.573 ccw(c-31.782,-13.214) -30.378,-13.271 ccw(c-31.862,-13.21) -30.397,-12.964 ccw(c-31.864,-13.209) -30.479,-12.667 ccw(c-31.796,-13.181) -30.623,-12.393 ccw(c-31.715,-13.126) -30.826,-12.157 ccw(c-31.74,-13.16) -31.08,-11.974 ccw(c-31.798,-13.263) -31.37,-11.851 ccw(c-31.817,-13.322) -31.68,-11.79 ccw(c-31.816,-13.298) -31.998,-11.795 ccw(c-31.827,-13.209) -32.308,-11.869 ccw(c-31.839,-13.162) -32.841,-12.22 ccw(c-31.722,-13.282) -33.038,-12.477 ccw(c-31.708,-13.295) -33.256,-13.088 ccw(c-31.836,-13.275) -33.262,-13.415 ccw(c-31.886,-13.278) -33.19,-13.738 ccw(c-31.766,-13.235) -33.046,-14.036 ccw(c-31.684,-13.185) -32.841,-14.299 ccw(c-31.674,-13.177) -32.585,-14.515 ccw(c-31.713,-13.236) -32.289,-14.673 ccw(c-31.753,-13.337) -31.963,-14.761 ccw(c-31.756,-13.322) -31.625,-14.77 ccw(c-31.767,-13.192) -31.291,-14.703 ccw(c-31.789,-13.118) -30.976,-14.567 ccw(c-31.781,-13.13) -30.695,-14.368 ccw(c-31.721,-13.197) -30.463,-14.114 ccw(c-31.635,-13.26) -30.294,-13.811 ccw(c-31.711,-13.232) -30.199,-13.477 ccw(c-31.834,-13.211) -30.18,-13.127 ccw(c-31.872,-13.211) -30.359,-12.449 ccw(c-31.754,-13.153) -30.553,-12.154 ccw(c-31.692,-13.104) -30.812,-11.91 ccw(c-31.767,-13.207) -31.121,-11.731 ccw(c-31.813,-13.309) -31.464,-11.622 ccw(c-31.819,-13.335) -31.823,-11.586 ccw(c-31.821,-13.268) -32.182,-11.625 ccw(c-31.846,-13.155) -32.525,-11.743 ccw(c-31.85,-13.136) -32.833,-11.94 ccw(c-31.761,-13.245) -33.089,-12.202 ccw(c-31.688,-13.304) -33.286,-12.514 ccw(c-31.69,-13.305) -33.415,-12.861 ccw(c-31.777,-13.283) -33.467,-13.228 ccw(c-31.897,-13.279) -33.435,-13.599 ccw(c-31.843,-13.264) -33.317,-13.954 ccw(c-31.718,-13.206) -33.122,-14.275 ccw(c-31.661,-13.164) -32.863,-14.551 ccw(c-31.681,-13.189) -32.553,-14.768 ccw(c-31.733,-13.284) -32.202,-14.913 ccw(c-31.755,-13.335) -31.443,-14.946 ccw(c-31.782,-13.141) -31.074,-14.835 ccw(c-31.786,-13.123) -30.439,-14.398 ccw(c-31.673,-13.233) -30.206,-14.086 ccw(c-31.628,-13.264) -30.052,-13.727 ccw(c-31.771,-13.222) -29.984,-13.34 ccw(c-31.881,-13.213) -29.998,-12.946 ccw(c-31.893,-13.213) -30.094,-12.561 ccw(c-31.812,-13.183) -30.268,-12.205 ccw(c-31.703,-13.113) -30.52,-11.896 ccw(c-31.714,-13.133) -30.838,-11.653 ccw(c-31.792,-13.263) -31.203,-11.487 ccw(c-31.821,-13.346) -31.598,-11.399 ccw(c-31.82,-13.326) -32.003,-11.395 ccw(c-31.832,-13.217) -32.4,-11.478 ccw(c-31.87,-13.098) -32.77,-11.65 ccw(c-31.815,-13.181) -33.09,-11.905 ccw(c-31.714,-13.283) -33.349,-12.224 ccw(c-31.682,-13.308) -33.645,-12.992 ccw(c-31.839,-13.28) -33.664,-13.406 ccw(c-31.928,-13.284) -33.585,-13.816 ccw(c-31.785,-13.238) -33.413,-14.198 ccw(c-31.674,-13.174) -33.163,-14.536 ccw(c-31.652,-13.156) -32.848,-14.817 ccw(c-31.699,-13.223) -32.48,-15.026 ccw(c-31.753,-13.349) -32.074,-15.148 ccw(c-31.761,-13.364) -31.648,-15.172 ccw(c-31.771,-13.201) -31.227,-15.099 ccw(c-31.799,-13.099) -30.828,-14.938 ccw(c-31.795,-13.103) -30.469,-14.699 ccw(c-31.725,-13.185) -30.169,-14.388 ccw(c-31.614,-13.271) -29.946,-14.016 ccw(c-31.681,-13.247) -29.817,-13.601 ccw(c-31.836,-13.216) -29.781,-13.165 ccw(c-31.901,-13.215) -29.982,-12.313 ccw(c-31.759,-13.15) -30.213,-11.938 ccw(c-31.707,-13.121) -30.905,-11.392 ccw(c-31.812,-13.32) -31.327,-11.245 ccw(c-31.821,-13.334) -32.219,-11.225 ccw(c-31.852,-13.15) -32.648,-11.36 ccw(c-31.85,-13.139) -33.037,-11.592 ccw(c-31.758,-13.26) -33.366,-11.906 ccw(c-31.715,-13.3) -33.793,-12.708 ccw(c-31.861,-13.257) -33.868,-13.161 ccw(c-31.851,-13.251) -33.836,-13.62 ccw(c-31.711,-13.226) -33.703,-14.063 ccw(c-31.687,-13.221) -33.174,-14.821 ccw(c-31.807,-13.344) -32.798,-15.097 ccw(c-31.775,-13.279) -32.366,-15.279 ccw(c-31.737,-13.155) -31.904,-15.364 ccw(c-31.734,-13.129) -31.432,-15.35 ccw(c-31.721,-13.215) -30.974,-15.236 ccw(c-31.7,-13.288) -30.187,-14.714 ccw(c-31.829,-13.153) -29.896,-14.334 ccw(c-31.829,-13.151) -29.691,-13.901 ccw(c-31.728,-13.185) -29.583,-13.433 ccw(c-31.633,-13.199) -29.584,-12.951 ccw(c-31.785,-13.217) -29.694,-12.48 ccw(c-31.875,-13.247) -29.903,-12.041 ccw(c-31.853,-13.232) -30.2,-11.655 ccw(c-31.765,-13.146) -30.574,-11.342 ccw(c-31.738,-13.115) -31.011,-11.123 ccw(c-31.793,-13.263) -31.489,-11.005 ccw(c-31.803,-13.316) -32.468,-11.08 ccw(c-31.849,-13.152) -32.924,-11.276 ccw(c-31.831,-13.172) -33.323,-11.571 ccw(c-31.73,-13.282) -33.65,-11.949 ccw(c-31.72,-13.295) -34.035,-12.869 ccw(c-31.904,-13.257) -34.067,-13.371 ccw(c-31.812,-13.248) -33.983,-13.869 ccw(c-31.682,-13.212) -33.793,-14.339 ccw(c-31.663,-13.204) -33.507,-14.76 ccw(c-31.738,-13.269) -33.138,-15.111 ccw(c-31.786,-13.318) -32.208,-15.524 ccw(c-31.738,-13.127) -31.695,-15.569 ccw(c-31.736,-13.133) -31.183,-15.506 ccw(c-31.708,-13.25) -30.696,-15.334 ccw(c-31.671,-13.333) -30.259,-15.053 ccw(c-31.777,-13.204) -29.895,-14.681 ccw(c-31.851,-13.144) -29.617,-14.239 ccw(c-31.819,-13.157) -29.438,-13.747 ccw(c-31.686,-13.189) -29.37,-13.227 ccw(c-31.658,-13.196) -29.423,-12.703 ccw(c-31.822,-13.231) -29.592,-12.202 ccw(c-31.866,-13.247) -30.224,-11.358 ccw(c-31.74,-13.106) -30.664,-11.057 ccw(c-31.755,-13.15) -31.163,-10.866 ccw(c-31.796,-13.3) -31.693,-10.787 ccw(c-31.8,-13.344) -32.23,-10.821 ccw(c-31.816,-13.257) -32.748,-10.968 ccw(c-31.874,-13.115) -33.221,-11.229 ccw(c-31.805,-13.205) -33.623,-11.592 ccw(c-31.701,-13.299) -33.94,-12.034 ccw(c-31.689,-13.308) -34.157,-12.535 ccw(c-31.797,-13.276) -34.262,-13.07 ccw(c-31.856,-13.26) -34.1,-14.149 ccw(c-31.659,-13.196) -33.846,-14.639 ccw(c-31.67,-13.205) -33.495,-15.066 ccw(c-31.762,-13.301) -33.059,-15.407 ccw(c-31.81,-13.37) -32.554,-15.64 ccw(c-31.753,-13.199) -32.009,-15.756 ccw(c-31.742,-13.105) -31.45,-15.753 ccw(c-31.735,-13.149) -30.902,-15.633 ccw(c-31.686,-13.291) -30.394,-15.395 ccw(c-31.686,-13.305) -29.952,-15.046 ccw(c-31.809,-13.179) -29.596,-14.606 ccw(c-31.84,-13.154) -29.196,-13.551 ccw(c-31.635,-13.188) -29.178,-12.982 ccw(c-31.701,-13.2) -29.291,-12.422 ccw(c-31.855,-13.249) -29.524,-11.899 ccw(c-31.89,-13.266) -29.862,-11.434 ccw(c-31.816,-13.198) -30.292,-11.052 ccw(c-31.723,-13.066) -30.799,-10.775 ccw(c-31.77,-13.192) -31.356,-10.62 ccw(c-31.795,-13.334) -31.936,-10.588 ccw(c-31.796,-13.342) -32.511,-10.679 ccw(c-31.83,-13.221) -33.054,-10.891 ccw(c-31.89,-13.103) -33.536,-11.223 ccw(c-31.772,-13.237) -33.932,-11.655 ccw(c-31.675,-13.309) -34.228,-12.164 ccw(c-31.698,-13.301) -34.412,-12.724 ccw(c-31.842,-13.272) -34.469,-13.312 ccw(c-31.914,-13.268) -34.39,-13.899 ccw(c-31.729,-13.221) -34.182,-14.456 ccw(c-31.659,-13.191) -33.439,-15.381 ccw(c-31.788,-13.345) -32.935,-15.702 ccw(c-31.792,-13.335) -32.368,-15.9 ccw(c-31.75,-13.157) -31.77,-15.969 ccw(c-31.744,-13.127) -30.593,-15.725 ccw(c-31.657,-13.335) -30.071,-15.416 ccw(c-31.716,-13.268) -29.633,-14.995 ccw(c-31.843,-13.16) -29.296,-14.487 ccw(c-31.872,-13.143) -29.071,-13.918 ccw(c-31.762,-13.172) -28.973,-13.314 ccw(c-31.659,-13.185) -29.193,-12.113 ccw(c-31.883,-13.268) -29.496,-11.574 ccw(c-31.884,-13.266) -29.905,-11.11 ccw(c-31.791,-13.163) -30.405,-10.744 ccw(c-31.725,-13.054) -30.977,-10.501 ccw(c-31.779,-13.24) -31.591,-10.392 ccw(c-31.789,-13.361) -32.216,-10.416 ccw(c-31.796,-13.328) -32.823,-10.571 ccw(c-31.853,-13.178) -33.382,-10.854 ccw(c-31.879,-13.126) -33.863,-11.26 ccw(c-31.734,-13.264) -34.244,-11.763 ccw(c-31.678,-13.303) -34.65,-12.956 ccw(c-31.896,-13.275) -34.651,-13.591 ccw(c-31.869,-13.263) -34.505,-14.211 ccw(c-31.69,-13.201) -34.226,-14.786 ccw(c-31.67,-13.196) -33.339,-15.701 ccw(c-31.809,-13.395) -32.765,-15.992 ccw(c-31.776,-13.287) -32.139,-16.144 ccw(c-31.752,-13.118) -31.492,-16.158 ccw(c-31.752,-13.091) -30.856,-16.035 ccw(c-31.714,-13.212) -30.259,-15.779 ccw(c-31.676,-13.299) -29.31,-14.899 ccw(c-31.874,-13.148) -29,-14.323 ccw(c-31.865,-13.149) -28.817,-13.693 ccw(c-31.714,-13.174) -28.774,-13.038 ccw(c-31.594,-13.173) -28.882,-12.389 ccw(c-31.795,-13.231) -29.133,-11.778 ccw(c-31.902,-13.287) -29.509,-11.233 ccw(c-31.87,-13.256) -29.992,-10.779 ccw(c-31.765,-13.116) -30.564,-10.44 ccw(c-31.742,-13.083) -31.199,-10.24 ccw(c-31.782,-13.288) -31.865,-10.186 ccw(c-31.786,-13.348) -33.16,-10.499 ccw(c-31.887,-13.13) -33.728,-10.86 ccw(c-31.848,-13.165) -34.198,-11.342 ccw(c-31.695,-13.286) -34.553,-11.917 ccw(c-31.646,-13.312) -34.781,-12.555 ccw(c-31.755,-13.288) -34.867,-13.228 ccw(c-31.95,-13.284) -34.801,-13.904 ccw(c-31.817,-13.25) -34.582,-14.549 ccw(c-31.658,-13.177) -34.228,-15.134 ccw(c-31.642,-13.168) -33.758,-15.633 ccw(c-31.732,-13.276) -33.192,-16.019 ccw(c-31.781,-13.342) -31.869,-16.367 ccw(c-31.759,-13.085) -31.179,-16.317 ccw(c-31.753,-13.103) -30.514,-16.124 ccw(c-31.688,-13.257) -29.906,-15.791 ccw(c-31.63,-13.349) -29.389,-15.327 ccw(c-31.796,-13.202) -28.987,-14.757 ccw(c-31.899,-13.143) -28.714,-14.114 ccw(c-31.845,-13.157) -28.582,-13.426 ccw(c-31.656,-13.171) -28.604,-12.725 ccw(c-31.636,-13.177) -28.787,-12.047 ccw(c-31.839,-13.255) -29.115,-11.423 ccw(c-31.883,-13.278) -30.126,-10.446 ccw(c-31.742,-13.059) -30.768,-10.146 ccw(c-31.758,-13.135) -31.464,-10 ccw(c-31.779,-13.334) -32.176,-10.008 ccw(c-31.776,-13.382) -32.873,-10.167 ccw(c-31.818,-13.264) -33.52,-10.47 ccw(c-31.924,-13.091) -34.085,-10.911 ccw(c-31.806,-13.203) -34.534,-11.471 ccw(c-31.658,-13.3) -34.855,-12.117 ccw(c-31.649,-13.306) -35.033,-12.816 ccw(c-31.803,-13.285) -35.057,-13.538 ccw(c-31.971,-13.296) -34.916,-14.249 ccw(c-31.765,-13.228) -34.618,-14.91 ccw(c-31.635,-13.154) -34.185,-15.496 ccw(c-31.655,-13.176) -33.637,-15.978 ccw(c-31.759,-13.326) -32.998,-16.33 ccw(c-31.801,-13.41) -32.293,-16.528 ccw(c-31.763,-13.179) -31.56,-16.563 ccw(c-31.764,-13.086) -30.149,-16.172 ccw(c-31.651,-13.308) -29.539,-15.757 ccw(c-31.661,-13.311) -29.039,-15.212 ccw(c-31.842,-13.178) -28.671,-14.568 ccw(c-31.873,-13.157) -28.373,-13.119 ccw(c-31.593,-13.159) -28.469,-12.38 ccw(c-31.693,-13.192) -28.732,-11.68 ccw(c-31.875,-13.283) -29.141,-11.052 ccw(c-31.909,-13.307) -29.674,-10.523 ccw(c-31.823,-13.197) -30.308,-10.119 ccw(c-31.73,-13.01) -31.018,-9.868 ccw(c-31.768,-13.194) -31.769,-9.784 ccw(c-31.771,-13.373) -32.522,-9.864 ccw(c-31.773,-13.374) -33.243,-10.1 ccw(c-31.845,-13.218) -33.897,-10.485 ccw(c-31.938,-13.087) -34.447,-11.011 ccw(c-31.757,-13.237) -34.867,-11.648 ccw(c-31.627,-13.306) -35.142,-12.362 ccw(c-31.667,-13.298) -35.261,-13.119 ccw(c-31.864,-13.29) -35.213,-13.884 ccw(c-31.939,-13.295) -34.991,-14.62 ccw(c-31.716,-13.2) -34.61,-15.29 ccw(c-31.644,-13.155) -33.469,-16.321 ccw(c-31.783,-13.388) -32.758,-16.627 ccw(c-31.784,-13.356) -31.993,-16.763 ccw(c-31.768,-13.127) -31.215,-16.728 ccw(c-31.764,-13.102) -29.764,-16.176 ccw(c-31.606,-13.355) -29.163,-15.675 ccw(c-31.707,-13.269) -28.692,-15.048 ccw(c-31.885,-13.162) -28.366,-14.333 ccw(c-31.915,-13.149) -28.197,-13.563 ccw(c-31.761,-13.164) -28.196,-12.775 ccw(c-31.641,-13.163) -28.721,-11.294 ccw(c-31.903,-13.311) -29.215,-10.671 ccw(c-31.898,-13.302) -29.829,-10.165 ccw(c-31.797,-13.145) -30.537,-9.804 ccw(c-31.739,-13.007) -31.312,-9.612 ccw(c-31.771,-13.255) -32.112,-9.599 ccw(c-31.76,-13.401) -32.898,-9.757 ccw(c-31.778,-13.351) -33.635,-10.076 ccw(c-31.884,-13.167) -34.285,-10.549 ccw(c-31.914,-13.121) -34.81,-11.159 ccw(c-31.706,-13.263) -35.189,-11.873 ccw(c-31.641,-13.296) -35.46,-13.46 ccw(c-31.933,-13.304) -35.331,-14.262 ccw(c-31.88,-13.279) -35.021,-15.013 ccw(c-31.674,-13.167) -34.554,-15.681 ccw(c-31.66,-13.167) -33.252,-16.654 ccw(c-31.798,-13.451) -32.471,-16.904 ccw(c-31.773,-13.292) -31.653,-16.969 ccw(c-31.778,-13.082) -30.838,-16.855 ccw(c-31.781,-13.059) -30.063,-16.573 ccw(c-31.704,-13.211) -29.366,-16.132 ccw(c-31.651,-13.301) -28.352,-14.836 ccw(c-31.922,-13.154) -28.079,-14.051 ccw(c-31.901,-13.156) -27.977,-13.225 ccw(c-31.699,-13.158) -28.055,-12.396 ccw(c-31.565,-13.137) -28.321,-11.605 ccw(c-31.804,-13.249) -28.758,-10.892 ccw(c-31.919,-13.334) -29.338,-10.286 ccw(c-31.879,-13.282) -30.032,-9.814 ccw(c-31.773,-13.08) -30.814,-9.506 ccw(c-31.755,-13.055) -31.648,-9.385 ccw(c-31.765,-13.314) -32.489,-9.45 ccw(c-31.761,-13.374) -34.043,-10.1 ccw(c-31.936,-13.114) -34.678,-10.663 ccw(c-31.864,-13.165) -35.167,-11.358 ccw(c-31.655,-13.281) -35.495,-12.145 ccw(c-31.6,-13.301) -35.65,-12.984 ccw(c-31.749,-13.292) -35.624,-13.838 ccw(c-31.993,-13.326) -35.406,-14.666 ccw(c-31.818,-13.251) -35.005,-15.424 ccw(c-31.642,-13.134) -34.448,-16.08 ccw(c-31.63,-13.127) -33.766,-16.606 ccw(c-31.726,-13.287) -32.986,-16.973 ccw(c-31.795,-13.479) -32.141,-17.154 ccw(c-31.772,-13.224) -31.276,-17.14 ccw(c-31.792,-13.048) -30.431,-16.942 ccw(c-31.778,-13.078) -29.646,-16.57 ccw(c-31.662,-13.263) -28.959,-16.037 ccw(c-31.587,-13.353) -28.411,-15.359 ccw(c-31.819,-13.204) -28.027,-14.575 ccw(c-31.923,-13.161) -27.79,-12.849 ccw(c-31.627,-13.142) -27.956,-11.988 ccw(c-31.623,-13.152) -28.316,-11.186 ccw(c-31.851,-13.286) -28.845,-10.481 ccw(c-31.891,-13.311) -30.286,-9.475 ccw(c-31.756,-13.006) -31.137,-9.232 ccw(c-31.766,-13.124) -32.022,-9.19 ccw(c-31.752,-13.366) -32.898,-9.341 ccw(c-31.742,-13.415) -33.725,-9.673 ccw(c-31.822,-13.269) -34.462,-10.174 ccw(c-31.984,-13.079) -35.069,-10.829 ccw(c-31.804,-13.204) -35.512,-11.606 ccw(c-31.611,-13.29) -35.779,-12.463 ccw(c-31.61,-13.293) -35.86,-13.357 ccw(c-31.812,-13.299) -35.747,-14.249 ccw(c-32.003,-13.34) -35.434,-15.093 ccw(c-31.758,-13.215) -34.938,-15.847 ccw(c-31.621,-13.105) -34.292,-16.48 ccw(c-31.648,-13.144) -33.526,-16.964 ccw(c-31.749,-13.355) -32.673,-17.27 ccw(c-31.766,-13.376) -31.77,-17.374 ccw(c-31.764,-13.14) -30.864,-17.277 ccw(c-31.77,-13.095) -29.998,-16.99 ccw(c-31.701,-13.241) -29.213,-16.522 ccw(c-31.651,-13.32) -28.553,-15.889 ccw(c-31.83,-13.169) -28.047,-15.124 ccw(c-31.875,-13.143) -27.714,-14.267 ccw(c-31.721,-13.182) -27.573,-13.359 ccw(c-31.616,-13.194) -27.641,-12.44 ccw(c-31.849,-13.236) -27.909,-11.556 ccw(c-31.903,-13.256) -28.36,-10.749 ccw(c-31.777,-13.164) -28.975,-10.056 ccw(c-31.694,-13.082) -29.731,-9.519 ccw(c-31.811,-13.291) -30.588,-9.161 ccw(c-31.832,-13.351) -31.504,-8.992 ccw(c-31.823,-13.198) -32.435,-9.025 ccw(c-31.835,-13.07) -33.337,-9.266 ccw(c-31.748,-13.297) -34.165,-9.701 ccw(c-31.712,-13.355) -34.884,-10.304 ccw(c-31.821,-13.254) -35.456,-11.047 ccw(c-31.937,-13.176) -35.847,-11.901 ccw(c-31.705,-13.253) -36.041,-12.823 ccw(c-31.694,-13.264) -35.825,-14.687 ccw(c-31.92,-13.327) -35.414,-15.539 ccw(c-31.712,-13.196) -34.823,-16.28 ccw(c-31.69,-13.189) -33.239,-17.309 ccw(c-31.789,-13.412) -32.314,-17.537 ccw(c-31.757,-13.167) -31.361,-17.554 ccw(c-31.75,-13.138) -29.547,-16.985 ccw(c-31.636,-13.363) -28.777,-16.414 ccw(c-31.805,-13.182) -28.152,-15.686 ccw(c-31.83,-13.154) -27.429,-13.914 ccw(c-31.575,-13.21) -27.378,-12.951 ccw(c-31.822,-13.225) -27.542,-11.999 ccw(c-31.868,-13.229) -28.453,-10.302 ccw(c-31.657,-13.063) -29.166,-9.645 ccw(c-31.802,-13.262) -30.01,-9.161 ccw(c-31.831,-13.307) -31.91,-8.779 ccw(c-31.825,-13.032) -32.877,-8.91 ccw(c-31.764,-13.27) -33.793,-9.254 ccw(c-31.744,-13.328) -35.308,-10.483 ccw(c-31.859,-13.207) -36.148,-12.248 ccw(c-31.671,-13.272) -36.167,-14.21 ccw(c-31.847,-13.285) -35.337,-15.994 ccw(c-31.67,-13.177) -33.828,-17.267 ccw(c-31.775,-13.329) -31.913,-17.767 ccw(c-31.746,-13.115) -29.958,-17.413 ccw(c-31.691,-13.3) -28.341,-16.25 ccw(c-31.844,-13.136) -27.362,-14.507 ccw(c-31.657,-13.213) -27.227,-12.508 ccw(c-31.89,-13.228) -27.951,-10.631 ccw(c-31.706,-13.127) -29.414,-9.245 ccw(c-31.846,-13.323) -31.333,-8.602 ccw(c-31.807,-13.021) -32.353,-8.61 ccw(c-31.777,-13.233) -33.346,-8.847 ccw(c-31.742,-13.35) -35.074,-9.923 ccw(c-31.951,-13.126) -35.722,-10.718 ccw(c-31.775,-13.234) -36.176,-11.64 ccw(c-31.654,-13.284) -36.45,-13.67 ccw(c-31.96,-13.303) -36.248,-14.682 ccw(c-31.773,-13.238) -35.825,-15.625 ccw(c-31.65,-13.172) -34.427,-17.138 ccw(c-31.83,-13.421) -33.514,-17.631 ccw(c-31.765,-13.243) -32.511,-17.908 ccw(c-31.735,-13.075) -31.471,-17.962 ccw(c-31.728,-13.15) -30.442,-17.794 ccw(c-31.659,-13.394) -29.474,-17.403 ccw(c-31.751,-13.239) -28.617,-16.803 ccw(c-31.865,-13.104) -27.908,-16.032 ccw(c-31.807,-13.143) -27.378,-15.126 ccw(c-31.574,-13.246) -27.061,-14.125 ccw(c-31.741,-13.221) -26.977,-13.077 ccw(c-31.924,-13.223) -27.12,-12.032 ccw(c-31.863,-13.204) -27.482,-11.042 ccw(c-31.634,-13.09) -28.054,-10.154 ccw(c-31.752,-13.196) -28.813,-9.416 ccw(c-31.87,-13.344) -29.714,-8.858 ccw(c-31.848,-13.289) -30.714,-8.503 ccw(c-31.791,-13.04) -31.769,-8.377 ccw(c-31.782,-13.187) -32.827,-8.492 ccw(c-31.743,-13.378) -33.838,-8.833 ccw(c-31.768,-13.331) -34.754,-9.381 ccw(c-31.924,-13.128) -35.528,-10.118 ccw(c-31.815,-13.207) -36.117,-11.011 ccw(c-31.637,-13.301) -36.501,-12.013 ccw(c-31.684,-13.293) -36.663,-13.074 ccw(c-31.939,-13.284) -36.588,-14.146 ccw(c-31.821,-13.252) -36.274,-15.175 ccw(c-31.629,-13.172) -35.744,-16.115 ccw(c-31.661,-13.199) -35.025,-16.921 ccw(c-31.83,-13.39) -34.147,-17.55 ccw(c-31.786,-13.289) -33.147,-17.966 ccw(c-31.723,-13.085) -32.079,-18.157 ccw(c-31.722,-13.12) -30.994,-18.117 ccw(c-31.683,-13.371) -29.943,-17.84 ccw(c-31.728,-13.286) -28.98,-17.333 ccw(c-31.849,-13.102) -28.148,-16.628 ccw(c-31.825,-13.12) -27.483,-15.761 ccw(c-31.609,-13.249) -27.024,-14.769 ccw(c-31.69,-13.234) -26.8,-13.697 ccw(c-31.915,-13.209) -26.813,-12.6 ccw(c-31.892,-13.203) -27.059,-11.53 ccw(c-31.657,-13.119) -27.533,-10.538 ccw(c-31.708,-13.165) -28.219,-9.678 ccw(c-31.874,-13.327) -29.078,-8.985 ccw(c-31.867,-13.31) -30.065,-8.489 ccw(c-31.783,-13.078) -31.137,-8.221 ccw(c-31.778,-13.132) -32.244,-8.201 ccw(c-31.759,-13.369) -33.331,-8.422 ccw(c-31.766,-13.359) -34.348,-8.869 ccw(c-31.89,-13.148) -35.243,-9.528 ccw(c-31.855,-13.168) -35.968,-10.373 ccw(c-31.655,-13.307) -36.493,-11.357 ccw(c-31.661,-13.309) -36.798,-12.431 ccw(c-31.9,-13.271) -36.862,-13.547 ccw(c-31.878,-13.257) -36.672,-14.65 ccw(c-31.637,-13.19) -36.246,-15.688 ccw(c-31.634,-13.192) -35.609,-16.613 ccw(c-31.814,-13.351) -34.785,-17.377 ccw(c-31.819,-13.337) -33.809,-17.937 ccw(c-31.715,-13.104) -32.732,-18.272 ccw(c-31.71,-13.096) -31.607,-18.371 ccw(c-31.702,-13.332) -30.487,-18.223 ccw(c-31.713,-13.343) -29.427,-17.825 ccw(c-31.829,-13.109) -28.478,-17.206 ccw(c-31.836,-13.095) -27.681,-16.397 ccw(c-31.651,-13.238) -27.077,-15.435 ccw(c-31.636,-13.26) -26.706,-14.359 ccw(c-31.895,-13.199) -26.578,-13.227 ccw(c-31.917,-13.195) -26.693,-12.091 ccw(c-31.693,-13.144) -27.052,-11.007 ccw(c-31.652,-13.139) -27.647,-10.03 ccw(c-31.869,-13.304) -28.442,-9.205 ccw(c-31.89,-13.323) -29.396,-8.567 ccw(c-31.787,-13.121) -30.466,-8.15 ccw(c-31.761,-13.071) -31.604,-7.984 ccw(c-31.773,-13.349) -32.753,-8.072 ccw(c-31.77,-13.384) -33.859,-8.402 ccw(c-31.859,-13.18) -34.867,-8.963 ccw(c-31.89,-13.115) -35.725,-9.739 ccw(c-31.68,-13.305) -36.393,-10.685 ccw(c-31.645,-13.328) -36.846,-11.753 ccw(c-31.856,-13.268) -37.057,-12.894 ccw(c-31.941,-13.25) -37.006,-14.056 ccw(c-31.656,-13.208) -36.701,-15.179 ccw(c-31.609,-13.193) -36.164,-16.214 ccw(c-31.787,-13.315) -35.415,-17.109 ccw(c-31.866,-13.381) -34.483,-17.814 ccw(c-31.714,-13.13) -33.417,-18.298 ccw(c-31.693,-13.079) -32.271,-18.545 ccw(c-31.712,-13.289) -31.099,-18.538 ccw(c-31.709,-13.407) -29.955,-18.268 ccw(c-31.807,-13.127) -28.898,-17.752 ccw(c-31.838,-13.072) -27.972,-17.023 ccw(c-31.69,-13.218) -27.226,-16.11 ccw(c-31.585,-13.298) -26.703,-15.052 ccw(c-31.867,-13.194) -26.424,-13.902 ccw(c-31.935,-13.181) -26.397,-12.718 ccw(c-31.733,-13.161) -26.625,-11.555 ccw(c-31.59,-13.126) -27.109,-10.472 ccw(c-31.853,-13.279) -27.822,-9.52 ccw(c-31.912,-13.328) -28.721,-8.74 ccw(c-31.801,-13.163) -29.768,-8.171 ccw(c-31.732,-13.016) -30.918,-7.852 ccw(c-31.782,-13.32) -32.111,-7.794 ccw(c-31.781,-13.404) -33.292,-7.991 ccw(c-31.836,-13.218) -34.403,-8.438 ccw(c-31.913,-13.059) -35.387,-9.123 ccw(c-31.709,-13.292) -36.196,-10.01 ccw(c-31.708,-13.308) -37.166,-12.198 ccw(c-31.997,-13.23) -37.265,-13.399 ccw(c-31.686,-13.222) -37.097,-14.594 ccw(c-31.663,-13.229) -36.024,-16.746 ccw(c-31.916,-13.41) -35.157,-17.593 ccw(c-31.723,-13.164) -34.123,-18.228 ccw(c-31.699,-13.141) -31.769,-18.776 ccw(c-31.72,-13.462) -30.558,-18.648 ccw(c-31.787,-13.156) -29.404,-18.254 ccw(c-31.794,-13.114) -27.472,-16.782 ccw(c-31.552,-13.341) -26.796,-15.762 ccw(c-31.83,-13.198) -26.361,-14.616 ccw(c-31.877,-13.174) -26.264,-12.176 ccw(c-31.539,-13.129) -26.62,-10.999 ccw(c-31.825,-13.253) -27.229,-9.929 ccw(c-31.882,-13.28) -29.056,-8.291 ccw(c-31.697,-12.983) -30.196,-7.812 ccw(c-31.784,-13.28) -31.415,-7.598 ccw(c-31.799,-13.352) -33.854,-7.964 ccw(c-31.846,-13.144) -35.901,-9.347 ccw(c-31.688,-13.331) -37.18,-11.469 ccw(c-31.889,-13.233) -37.421,-13.94 ccw(c-31.633,-13.229) -36.596,-16.29 ccw(c-31.846,-13.327) -34.837,-18.06 ccw(c-31.68,-13.119) -32.489,-18.926 ccw(c-31.74,-13.356) -29.993,-18.698 ccw(c-31.799,-13.086) -27.818,-17.434 ccw(c-31.645,-13.289) -26.395,-15.355 ccw(c-31.901,-13.159) -25.981,-12.862 ccw(c-31.636,-13.169) -26.679,-10.429 ccw(c-31.908,-13.288) -28.345,-8.512 ccw(c-31.671,-12.984) -29.452,-7.871 ccw(c-31.774,-13.233) -30.675,-7.494 ccw(c-31.81,-13.376) -33.226,-7.555 ccw(c-31.894,-12.999) -34.431,-8.002 ccw(c-31.772,-13.228) -35.507,-8.708 ccw(c-31.677,-13.355) -37.093,-10.722 ccw(c-32.023,-13.18) -37.52,-11.941 ccw(c-31.778,-13.228) -37.662,-13.226 ccw(c-31.609,-13.236) -37.118,-15.744 ccw(c-31.963,-13.391) -36.448,-16.855 ccw(c-31.779,-13.239) -35.544,-17.788 ccw(c-31.659,-13.105) -33.246,-18.98 ccw(c-31.765,-13.477) -31.957,-19.172 ccw(c-31.765,-13.25) -30.656,-19.07 ccw(c-31.802,-13.037) -29.404,-18.691 ccw(c-31.763,-13.118) -28.262,-18.054 ccw(c-31.576,-13.378) -27.287,-17.179 ccw(c-31.742,-13.243) -26.532,-16.107 ccw(c-31.937,-13.132) -26.025,-14.895 ccw(c-31.855,-13.152) -25.787,-13.602 ccw(c-31.535,-13.173) -25.839,-12.288 ccw(c-31.731,-13.214) -26.186,-11.017 ccw(c-31.948,-13.295) -26.799,-9.848 ccw(c-31.887,-13.249) -27.647,-8.836 ccw(c-31.666,-13.016) -28.699,-8.035 ccw(c-31.752,-13.181) -29.905,-7.489 ccw(c-31.829,-13.407) -31.202,-7.216 ccw(c-31.827,-13.338) -32.529,-7.224 ccw(c-31.866,-13.019) -33.822,-7.525 ccw(c-31.798,-13.176) -35.017,-8.109 ccw(c-31.669,-13.386) -36.059,-8.938 ccw(c-31.715,-13.345) -36.902,-9.971 ccw(c-31.985,-13.173) -37.498,-11.164 ccw(c-31.835,-13.214) -37.811,-12.463 ccw(c-31.584,-13.25) -37.836,-13.801 ccw(c-31.638,-13.259) -37.576,-15.115 ccw(c-31.942,-13.357) -37.035,-16.34 ccw(c-31.829,-13.275) -36.23,-17.414 ccw(c-31.636,-13.099) -35.21,-18.29 ccw(c-31.659,-13.141) -34.027,-18.93 ccw(c-31.776,-13.435) -32.731,-19.296 ccw(c-31.77,-13.312) -31.385,-19.36 ccw(c-31.783,-13.044) -30.054,-19.132 ccw(c-31.768,-13.082) -28.8,-18.626 ccw(c-31.617,-13.358) -27.687,-17.857 ccw(c-31.697,-13.288) -26.775,-16.856 ccw(c-31.917,-13.123) -26.1,-15.68 ccw(c-31.886,-13.132) -25.69,-14.386 ccw(c-31.58,-13.191) -25.572,-13.032 ccw(c-31.667,-13.208) -25.762,-11.685 ccw(c-31.941,-13.275) -26.241,-10.409 ccw(c-31.921,-13.26) -26.98,-9.263 ccw(c-31.683,-13.063) -27.952,-8.305 ccw(c-31.714,-13.127) -29.116,-7.59 ccw(c-31.84,-13.387) -30.41,-7.144 ccw(c-31.841,-13.37) -31.771,-6.982 ccw(c-31.841,-13.064) -33.135,-7.121 ccw(c-31.815,-13.111) -34.433,-7.564 ccw(c-31.692,-13.381) -35.607,-8.28 ccw(c-31.701,-13.376) -36.604,-9.229 ccw(c-31.933,-13.184) -37.37,-10.374 ccw(c-31.897,-13.185) -37.858,-11.663 ccw(c-31.604,-13.264) -38.056,-13.03 ccw(c-31.606,-13.268) -37.958,-14.409 ccw(c-31.898,-13.324) -37.563,-15.734 ccw(c-31.892,-13.304) -36.879,-16.938 ccw(c-31.639,-13.124) -35.947,-17.965 ccw(c-31.631,-13.122) -34.817,-18.773 ccw(c-31.772,-13.38) -33.539,-19.316 ccw(c-31.789,-13.381) -32.169,-19.557 ccw(c-31.766,-13.064) -30.777,-19.494 ccw(c-31.764,-13.049) -29.429,-19.136 ccw(c-31.657,-13.318) -28.19,-18.495 ccw(c-31.656,-13.348) -27.126,-17.589 ccw(c-31.89,-13.124) -26.284,-16.471 ccw(c-31.907,-13.108) -25.698,-15.199 ccw(c-31.636,-13.196) -25.401,-13.829 ccw(c-31.593,-13.215) -25.421,-12.426 ccw(c-31.922,-13.254) -25.747,-11.059 ccw(c-31.953,-13.26) -26.357,-9.79 ccw(c-31.716,-13.109) -27.226,-8.684 ccw(c-31.66,-13.075) -28.325,-7.801 ccw(c-31.843,-13.358) -29.592,-7.178 ccw(c-31.861,-13.393) -30.964,-6.838 ccw(c-31.827,-13.119) -32.377,-6.803 ccw(c-31.82,-13.036) -33.764,-7.087 ccw(c-31.716,-13.363) -35.056,-7.669 ccw(c-31.696,-13.407) -36.198,-8.513 ccw(c-31.883,-13.209) -37.13,-9.584 ccw(c-31.959,-13.14) -37.797,-10.839 ccw(c-31.635,-13.271) -38.175,-12.212 ccw(c-31.581,-13.284) -38.252,-13.636 ccw(c-31.847,-13.302) -38.02,-15.043 ccw(c-31.967,-13.322) -37.476,-16.363 ccw(c-31.654,-13.153) -36.655,-17.534 ccw(c-31.603,-13.114) -35.603,-18.505 ccw(c-31.756,-13.327) -34.366,-19.226 ccw(c-31.824,-13.449) -32.996,-19.651 ccw(c-31.754,-13.096) -31.564,-19.765 ccw(c-31.751,-13.023) -30.139,-19.572 ccw(c-31.686,-13.271) -28.789,-19.076 ccw(c-31.627,-13.418) -27.584,-18.288 ccw(c-31.857,-13.136) -26.579,-17.253 ccw(c-31.918,-13.082) -25.817,-16.027 ccw(c-31.691,-13.187) -25.336,-14.665 ccw(c-31.522,-13.239) -25.174,-13.228 ccw(c-31.89,-13.236) -25.332,-11.788 ccw(c-31.979,-13.251) -25.792,-10.413 ccw(c-31.758,-13.145) -26.539,-9.169 ccw(c-31.597,-13.036) -27.547,-8.123 ccw(c-31.835,-13.321) -28.762,-7.324 ccw(c-31.884,-13.407) -30.121,-6.801 ccw(c-31.827,-13.174) -31.561,-6.582 ccw(c-31.808,-12.964) -33.015,-6.692 ccw(c-31.74,-13.332) -34.411,-7.121 ccw(c-31.702,-13.432) -35.686,-7.838 ccw(c-31.841,-13.244) -36.778,-8.812 ccw(c-32.004,-13.085) -37.623,-10.008 ccw(c-31.675,-13.268) -38.185,-11.363 ccw(c-31.66,-13.288) -38.391,-14.276 ccw(c-32.035,-13.321) -38.007,-15.696 ccw(c-31.684,-13.183) -37.319,-16.998 ccw(c-31.649,-13.177) -35.196,-19.022 ccw(c-31.869,-13.498) -33.852,-19.634 ccw(c-31.751,-13.139) -32.404,-19.934 ccw(c-31.732,-13.096) -29.479,-19.587 ccw(c-31.62,-13.481) -28.145,-18.939 ccw(c-31.822,-13.162) -26.986,-18.011 ccw(c-31.852,-13.112) -25.383,-15.526 ccw(c-31.472,-13.273) -25.03,-14.079 ccw(c-31.846,-13.226) -25.007,-12.588 ccw(c-31.916,-13.219) -25.903,-9.757 ccw(c-31.541,-13.023) -26.797,-8.558 ccw(c-31.813,-13.28) -27.935,-7.586 ccw(c-31.87,-13.34) -30.7,-6.468 ccw(c-31.791,-13.096) -33.68,-6.649 ccw(c-31.744,-13.381) -36.314,-8.073 ccw(c-31.891,-13.155) -38.081,-10.495 ccw(c-31.629,-13.306) -38.665,-13.444 ccw(c-31.91,-13.278) -37.923,-16.361 ccw(c-31.616,-13.165) -36.015,-18.701 ccw(c-31.823,-13.375) -33.283,-19.993 ccw(c-31.72,-13.064) -30.252,-20.014 ccw(c-31.686,-13.369) -27.503,-18.728 ccw(c-31.867,-13.082) -25.548,-16.396 ccw(c-31.599,-13.254) -24.783,-13.447 ccw(c-31.948,-13.211) -25.336,-10.442 ccw(c-31.634,-13.108) -27.128,-7.963 ccw(c-31.897,-13.359) -29.807,-6.468 ccw(c-31.753,-12.914) -31.327,-6.194 ccw(c-31.766,-13.229) -32.871,-6.268 ccw(c-31.747,-13.413) -35.742,-7.383 ccw(c-31.998,-13.018) -36.927,-8.384 ccw(c-31.773,-13.22) -37.858,-9.625 ccw(c-31.608,-13.328) -38.832,-12.56 ccw(c-32.072,-13.271) -38.817,-14.117 ccw(c-31.786,-13.227) -38.452,-15.632 ccw(c-31.585,-13.164) -36.805,-18.263 ccw(c-31.924,-13.485) -35.591,-19.248 ccw(c-31.784,-13.248) -34.186,-19.935 ccw(c-31.693,-13.009) -32.663,-20.306 ccw(c-31.703,-13.12) -31.096,-20.344 ccw(c-31.668,-13.504) -29.558,-20.036 ccw(c-31.758,-13.261) -28.126,-19.389 ccw(c-31.889,-13.03) -26.866,-18.448 ccw(c-31.815,-13.103) -25.833,-17.26 ccw(c-31.496,-13.321) -25.087,-15.873 ccw(c-31.726,-13.242) -24.672,-14.352 ccw(c-31.996,-13.195) -24.593,-12.775 ccw(c-31.901,-13.185) -24.851,-11.216 ccw(c-31.53,-13.078) -25.447,-9.751 ccw(c-31.722,-13.197) -26.357,-8.456 ccw(c-31.937,-13.381) -27.527,-7.386 ccw(c-31.889,-13.308) -28.898,-6.589 ccw(c-31.735,-12.954) -30.412,-6.112 ccw(c-31.761,-13.161) -31.996,-5.988 ccw(c-31.757,-13.452) -33.572,-6.208 ccw(c-31.781,-13.377) -35.067,-6.758 ccw(c-31.954,-13.034) -36.405,-7.624 ccw(c-31.823,-13.171) -37.514,-8.77 ccw(c-31.589,-13.358) -38.352,-10.13 ccw(c-31.654,-13.333) -38.883,-11.638 ccw(c-32.027,-13.249) -39.069,-13.227 ccw(c-31.857,-13.234) -38.893,-14.818 ccw(c-31.556,-13.171) -38.377,-16.337 ccw(c-31.608,-13.201) -37.55,-17.712 ccw(c-31.91,-13.434) -36.441,-18.873 ccw(c-31.826,-13.308) -35.097,-19.755 ccw(c-31.678,-13.028) -33.592,-20.327 ccw(c-31.686,-13.08) -31.999,-20.567 ccw(c-31.698,-13.457) -30.391,-20.452 ccw(c-31.739,-13.332) -28.849,-19.978 ccw(c-31.864,-13.033) -27.444,-19.18 ccw(c-31.835,-13.064) -26.239,-18.101 ccw(c-31.554,-13.312) -25.299,-16.784 ccw(c-31.658,-13.274) -24.679,-15.288 ccw(c-31.976,-13.178) -24.398,-13.69 ccw(c-31.943,-13.175) -24.461,-12.068 ccw(c-31.577,-13.117) -24.878,-10.498 ccw(c-31.652,-13.165) -25.639,-9.062 ccw(c-31.936,-13.354) -26.694,-7.822 ccw(c-31.924,-13.333) -27.99,-6.833 ccw(c-31.737,-13.017) -29.471,-6.151 ccw(c-31.74,-13.085) -31.068,-5.82 ccw(c-31.777,-13.433) -32.703,-5.843 ccw(c-31.784,-13.419) -34.296,-6.213 ccw(c-31.907,-13.078) -35.771,-6.921 ccw(c-31.868,-13.105) -37.05,-7.945 ccw(c-31.618,-13.361) -38.077,-9.224 ccw(c-31.625,-13.362) -38.81,-10.693 ccw(c-31.962,-13.242) -39.206,-12.287 ccw(c-31.938,-13.226) -39.233,-13.931 ccw(c-31.574,-13.195) -38.901,-15.544 ccw(c-31.568,-13.199) -38.234,-17.051 ccw(c-31.871,-13.379) -37.254,-18.377 ccw(c-31.885,-13.366) -36,-19.45 ccw(c-31.672,-13.059) -34.54,-20.225 ccw(c-31.662,-13.048) -32.948,-20.672 ccw(c-31.716,-13.392) -31.295,-20.764 ccw(c-31.733,-13.417) -29.663,-20.48 ccw(c-31.836,-13.05) -28.13,-19.847 ccw(c-31.842,-13.027) -26.765,-18.901 ccw(c-31.616,-13.282) -25.637,-17.682 ccw(c-31.589,-13.325) -24.813,-16.239 ccw(c-31.944,-13.167) -24.322,-14.648 ccw(c-31.976,-13.156) -24.18,-12.987 ccw(c-31.64,-13.144) -24.401,-11.335 ccw(c-31.568,-13.145) -24.989,-9.773 ccw(c-31.922,-13.322) -25.906,-8.376 ccw(c-31.959,-13.345) -27.099,-7.204 ccw(c-31.757,-13.083) -28.518,-6.318 ccw(c-31.701,-13.007) -30.103,-5.774 ccw(c-31.792,-13.4) -31.77,-5.589 ccw(c-31.798,-13.452) -33.44,-5.762 ccw(c-31.87,-13.136) -35.033,-6.292 ccw(c-31.903,-13.024) -36.467,-7.169 ccw(c-31.654,-13.35) -37.676,-8.34 ccw(c-31.609,-13.394) -38.611,-9.743 ccw(c-31.894,-13.251) -39.22,-11.314 ccw(c-32.023,-13.199) -39.459,-12.984 ccw(c-31.607,-13.216) -39.327,-14.668 ccw(c-31.535,-13.208) -38.84,-16.288 ccw(c-31.821,-13.333) -38.015,-17.764 ccw(c-31.96,-13.413) -36.877,-19.019 ccw(c-31.679,-13.099) -35.49,-19.994 ccw(c-31.634,-13.029) -33.926,-20.653 ccw(c-31.718,-13.324) -32.256,-20.959 ccw(c-31.745,-13.504) -30.558,-20.882 ccw(c-31.81,-13.081) -28.917,-20.433 ccw(c-31.838,-12.994) -27.407,-19.645 ccw(c-31.668,-13.24) -26.101,-18.549 ccw(c-31.531,-13.391) -25.075,-17.187 ccw(c-31.902,-13.169) -24.372,-15.631 ccw(c-31.997,-13.131) -24.016,-13.958 ccw(c-31.705,-13.157) -24.028,-12.249 ccw(c-31.481,-13.144) -24.424,-10.583 ccw(c-31.892,-13.289) -25.179,-9.044 ccw(c-31.99,-13.344) -26.244,-7.699 ccw(c-31.79,-13.141) -27.574,-6.615 ccw(c-31.647,-12.942) -29.115,-5.856 ccw(c-31.797,-13.354) -30.787,-5.455 ccw(c-31.818,-13.475) -32.509,-5.418 ccw(c-31.847,-13.198) -34.198,-5.752 ccw(c-31.916,-12.943) -35.771,-6.458 ccw(c-31.693,-13.323) -37.151,-7.495 ccw(c-31.694,-13.348) -39.103,-10.324 ccw(c-32.091,-13.158) -39.563,-11.992 ccw(c-31.654,-13.228) -39.644,-13.722 ccw(c-31.621,-13.243) -38.705,-17.04 ccw(c-32.034,-13.436) -37.711,-18.463 ccw(c-31.701,-13.144) -36.424,-19.633 ccw(c-31.66,-13.116) -33.258,-21.029 ccw(c-31.776,-13.572) -31.521,-21.171 ccw(c-31.789,-13.129) -29.794,-20.924 ccw(c-31.788,-13.066) -26.689,-19.368 ccw(c-31.536,-13.418) -25.467,-18.116 ccw(c-31.858,-13.164) -24.551,-16.624 -23.89,-15.963 -23.782,-15.855 -23.373,-15.855 v2@-23.314,-15.796
  other v2: -23.19,-15.85 -22.327,-15.85 -23.089,-13.665 -23.063,-11.176 -22.225,-11.176

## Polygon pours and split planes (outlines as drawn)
Net1 on Bottom Layer "NET1_L04_P003" (solid, pour order 3): -40.665,-4.776 -15.342,-4.75 -14.173,-4.776 -14.169,-4.851 -14.173,-21.768 -40.665,-21.768
Net1 on Layer 2 "NET1_L03_P005" (solid, pour order 5): -40.665,-4.776 -15.342,-4.75 -14.173,-4.776 -14.169,-4.851 -14.173,-21.768 -40.665,-21.768
Net1 on Top Layer "NET1_L01_P002" (solid, pour order 2): -40.665,-4.776 -15.342,-4.75 -14.173,-4.776 -14.169,-4.851 -14.173,-21.768 -40.665,-21.768
Net1 on Layer 1 "NET1_L02_P004" (solid, pour order 4): -40.665,-4.776 -15.342,-4.75 -14.173,-4.776 -14.169,-4.851 -14.173,-21.768 -40.665,-21.768

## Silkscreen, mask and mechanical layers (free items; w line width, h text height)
Top Overlay:
  lines w0.2: -20.026,-15.989 -20.026,-16.414 -19.026,-16.414 ; -20.026,-11.189 -20.026,-10.764 -19.026,-10.764 ; -15.776,-16.414 -15.026,-16.414 -15.026,-10.764 -15.776,-10.764
  text "TYP-B 4-LAYER 35-COILS" at -27.127,-21.234 h0.8
Mechanical 2:
  the board outline again, w0.1
Mechanical 13:
  lines w0.1: -20.026,-16.414 -20.026,-10.764 -15.026,-10.764 -15.026,-16.414 -20.026,-16.414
